# Generated by FakeRAM 2.0
VERSION 5.7 ;
BUSBITCHARS "[]" ;
PROPERTYDEFINITIONS
  MACRO width INTEGER ;
  MACRO depth INTEGER ;
  MACRO banks INTEGER ;
END PROPERTYDEFINITIONS
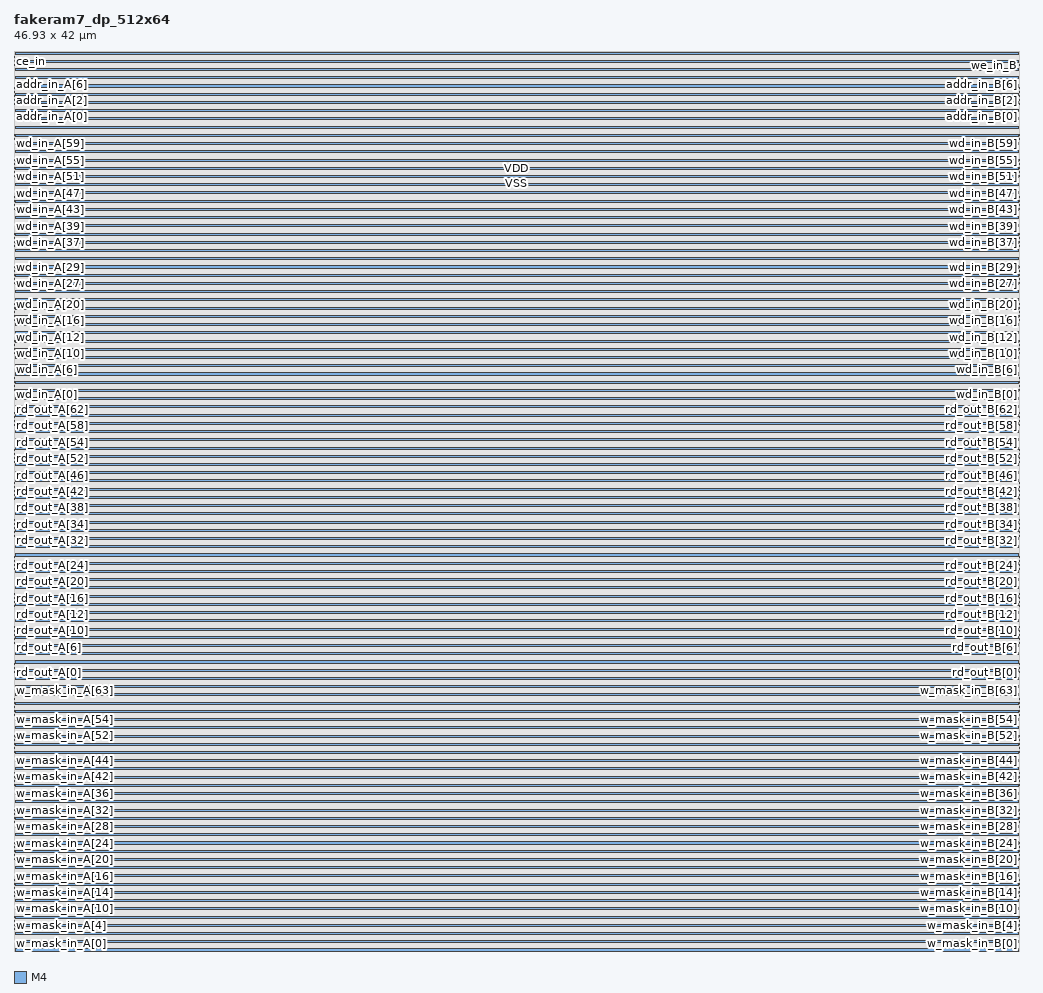
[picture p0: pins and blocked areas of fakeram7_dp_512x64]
MACRO fakeram7_dp_512x64
  PROPERTY width 64 ;
  PROPERTY depth 512 ;
  PROPERTY banks 4 ;
  FOREIGN fakeram7_dp_512x64 0 0 ;
  SYMMETRY X Y ;
  SIZE 46.930 BY 42.000 ;
  CLASS BLOCK ;
  PIN w_mask_in_A[0]
    DIRECTION INPUT ;
    USE SIGNAL ;
    SHAPE ABUTMENT ;
    PORT
      LAYER M4 ;
      RECT 0.000 0.048 0.024 0.072 ;
    END
  END w_mask_in_A[0]
  PIN w_mask_in_B[0]
    DIRECTION INPUT ;
    USE SIGNAL ;
    SHAPE ABUTMENT ;
    PORT
      LAYER M4 ;
      RECT 46.906 0.048 46.930 0.072 ;
    END
  END w_mask_in_B[0]
  PIN w_mask_in_A[1]
    DIRECTION INPUT ;
    USE SIGNAL ;
    SHAPE ABUTMENT ;
    PORT
      LAYER M4 ;
      RECT 0.000 0.240 0.024 0.264 ;
    END
  END w_mask_in_A[1]
  PIN w_mask_in_B[1]
    DIRECTION INPUT ;
    USE SIGNAL ;
    SHAPE ABUTMENT ;
    PORT
      LAYER M4 ;
      RECT 46.906 0.240 46.930 0.264 ;
    END
  END w_mask_in_B[1]
  PIN w_mask_in_A[2]
    DIRECTION INPUT ;
    USE SIGNAL ;
    SHAPE ABUTMENT ;
    PORT
      LAYER M4 ;
      RECT 0.000 0.432 0.024 0.456 ;
    END
  END w_mask_in_A[2]
  PIN w_mask_in_B[2]
    DIRECTION INPUT ;
    USE SIGNAL ;
    SHAPE ABUTMENT ;
    PORT
      LAYER M4 ;
      RECT 46.906 0.432 46.930 0.456 ;
    END
  END w_mask_in_B[2]
  PIN w_mask_in_A[3]
    DIRECTION INPUT ;
    USE SIGNAL ;
    SHAPE ABUTMENT ;
    PORT
      LAYER M4 ;
      RECT 0.000 0.624 0.024 0.648 ;
    END
  END w_mask_in_A[3]
  PIN w_mask_in_B[3]
    DIRECTION INPUT ;
    USE SIGNAL ;
    SHAPE ABUTMENT ;
    PORT
      LAYER M4 ;
      RECT 46.906 0.624 46.930 0.648 ;
    END
  END w_mask_in_B[3]
  PIN w_mask_in_A[4]
    DIRECTION INPUT ;
    USE SIGNAL ;
    SHAPE ABUTMENT ;
    PORT
      LAYER M4 ;
      RECT 0.000 0.816 0.024 0.840 ;
    END
  END w_mask_in_A[4]
  PIN w_mask_in_B[4]
    DIRECTION INPUT ;
    USE SIGNAL ;
    SHAPE ABUTMENT ;
    PORT
      LAYER M4 ;
      RECT 46.906 0.816 46.930 0.840 ;
    END
  END w_mask_in_B[4]
  PIN w_mask_in_A[5]
    DIRECTION INPUT ;
    USE SIGNAL ;
    SHAPE ABUTMENT ;
    PORT
      LAYER M4 ;
      RECT 0.000 1.008 0.024 1.032 ;
    END
  END w_mask_in_A[5]
  PIN w_mask_in_B[5]
    DIRECTION INPUT ;
    USE SIGNAL ;
    SHAPE ABUTMENT ;
    PORT
      LAYER M4 ;
      RECT 46.906 1.008 46.930 1.032 ;
    END
  END w_mask_in_B[5]
  PIN w_mask_in_A[6]
    DIRECTION INPUT ;
    USE SIGNAL ;
    SHAPE ABUTMENT ;
    PORT
      LAYER M4 ;
      RECT 0.000 1.200 0.024 1.224 ;
    END
  END w_mask_in_A[6]
  PIN w_mask_in_B[6]
    DIRECTION INPUT ;
    USE SIGNAL ;
    SHAPE ABUTMENT ;
    PORT
      LAYER M4 ;
      RECT 46.906 1.200 46.930 1.224 ;
    END
  END w_mask_in_B[6]
  PIN w_mask_in_A[7]
    DIRECTION INPUT ;
    USE SIGNAL ;
    SHAPE ABUTMENT ;
    PORT
      LAYER M4 ;
      RECT 0.000 1.392 0.024 1.416 ;
    END
  END w_mask_in_A[7]
  PIN w_mask_in_B[7]
    DIRECTION INPUT ;
    USE SIGNAL ;
    SHAPE ABUTMENT ;
    PORT
      LAYER M4 ;
      RECT 46.906 1.392 46.930 1.416 ;
    END
  END w_mask_in_B[7]
  PIN w_mask_in_A[8]
    DIRECTION INPUT ;
    USE SIGNAL ;
    SHAPE ABUTMENT ;
    PORT
      LAYER M4 ;
      RECT 0.000 1.584 0.024 1.608 ;
    END
  END w_mask_in_A[8]
  PIN w_mask_in_B[8]
    DIRECTION INPUT ;
    USE SIGNAL ;
    SHAPE ABUTMENT ;
    PORT
      LAYER M4 ;
      RECT 46.906 1.584 46.930 1.608 ;
    END
  END w_mask_in_B[8]
  PIN w_mask_in_A[9]
    DIRECTION INPUT ;
    USE SIGNAL ;
    SHAPE ABUTMENT ;
    PORT
      LAYER M4 ;
      RECT 0.000 1.776 0.024 1.800 ;
    END
  END w_mask_in_A[9]
  PIN w_mask_in_B[9]
    DIRECTION INPUT ;
    USE SIGNAL ;
    SHAPE ABUTMENT ;
    PORT
      LAYER M4 ;
      RECT 46.906 1.776 46.930 1.800 ;
    END
  END w_mask_in_B[9]
  PIN w_mask_in_A[10]
    DIRECTION INPUT ;
    USE SIGNAL ;
    SHAPE ABUTMENT ;
    PORT
      LAYER M4 ;
      RECT 0.000 1.968 0.024 1.992 ;
    END
  END w_mask_in_A[10]
  PIN w_mask_in_B[10]
    DIRECTION INPUT ;
    USE SIGNAL ;
    SHAPE ABUTMENT ;
    PORT
      LAYER M4 ;
      RECT 46.906 1.968 46.930 1.992 ;
    END
  END w_mask_in_B[10]
  PIN w_mask_in_A[11]
    DIRECTION INPUT ;
    USE SIGNAL ;
    SHAPE ABUTMENT ;
    PORT
      LAYER M4 ;
      RECT 0.000 2.160 0.024 2.184 ;
    END
  END w_mask_in_A[11]
  PIN w_mask_in_B[11]
    DIRECTION INPUT ;
    USE SIGNAL ;
    SHAPE ABUTMENT ;
    PORT
      LAYER M4 ;
      RECT 46.906 2.160 46.930 2.184 ;
    END
  END w_mask_in_B[11]
  PIN w_mask_in_A[12]
    DIRECTION INPUT ;
    USE SIGNAL ;
    SHAPE ABUTMENT ;
    PORT
      LAYER M4 ;
      RECT 0.000 2.352 0.024 2.376 ;
    END
  END w_mask_in_A[12]
  PIN w_mask_in_B[12]
    DIRECTION INPUT ;
    USE SIGNAL ;
    SHAPE ABUTMENT ;
    PORT
      LAYER M4 ;
      RECT 46.906 2.352 46.930 2.376 ;
    END
  END w_mask_in_B[12]
  PIN w_mask_in_A[13]
    DIRECTION INPUT ;
    USE SIGNAL ;
    SHAPE ABUTMENT ;
    PORT
      LAYER M4 ;
      RECT 0.000 2.544 0.024 2.568 ;
    END
  END w_mask_in_A[13]
  PIN w_mask_in_B[13]
    DIRECTION INPUT ;
    USE SIGNAL ;
    SHAPE ABUTMENT ;
    PORT
      LAYER M4 ;
      RECT 46.906 2.544 46.930 2.568 ;
    END
  END w_mask_in_B[13]
  PIN w_mask_in_A[14]
    DIRECTION INPUT ;
    USE SIGNAL ;
    SHAPE ABUTMENT ;
    PORT
      LAYER M4 ;
      RECT 0.000 2.736 0.024 2.760 ;
    END
  END w_mask_in_A[14]
  PIN w_mask_in_B[14]
    DIRECTION INPUT ;
    USE SIGNAL ;
    SHAPE ABUTMENT ;
    PORT
      LAYER M4 ;
      RECT 46.906 2.736 46.930 2.760 ;
    END
  END w_mask_in_B[14]
  PIN w_mask_in_A[15]
    DIRECTION INPUT ;
    USE SIGNAL ;
    SHAPE ABUTMENT ;
    PORT
      LAYER M4 ;
      RECT 0.000 2.928 0.024 2.952 ;
    END
  END w_mask_in_A[15]
  PIN w_mask_in_B[15]
    DIRECTION INPUT ;
    USE SIGNAL ;
    SHAPE ABUTMENT ;
    PORT
      LAYER M4 ;
      RECT 46.906 2.928 46.930 2.952 ;
    END
  END w_mask_in_B[15]
  PIN w_mask_in_A[16]
    DIRECTION INPUT ;
    USE SIGNAL ;
    SHAPE ABUTMENT ;
    PORT
      LAYER M4 ;
      RECT 0.000 3.120 0.024 3.144 ;
    END
  END w_mask_in_A[16]
  PIN w_mask_in_B[16]
    DIRECTION INPUT ;
    USE SIGNAL ;
    SHAPE ABUTMENT ;
    PORT
      LAYER M4 ;
      RECT 46.906 3.120 46.930 3.144 ;
    END
  END w_mask_in_B[16]
  PIN w_mask_in_A[17]
    DIRECTION INPUT ;
    USE SIGNAL ;
    SHAPE ABUTMENT ;
    PORT
      LAYER M4 ;
      RECT 0.000 3.312 0.024 3.336 ;
    END
  END w_mask_in_A[17]
  PIN w_mask_in_B[17]
    DIRECTION INPUT ;
    USE SIGNAL ;
    SHAPE ABUTMENT ;
    PORT
      LAYER M4 ;
      RECT 46.906 3.312 46.930 3.336 ;
    END
  END w_mask_in_B[17]
  PIN w_mask_in_A[18]
    DIRECTION INPUT ;
    USE SIGNAL ;
    SHAPE ABUTMENT ;
    PORT
      LAYER M4 ;
      RECT 0.000 3.504 0.024 3.528 ;
    END
  END w_mask_in_A[18]
  PIN w_mask_in_B[18]
    DIRECTION INPUT ;
    USE SIGNAL ;
    SHAPE ABUTMENT ;
    PORT
      LAYER M4 ;
      RECT 46.906 3.504 46.930 3.528 ;
    END
  END w_mask_in_B[18]
  PIN w_mask_in_A[19]
    DIRECTION INPUT ;
    USE SIGNAL ;
    SHAPE ABUTMENT ;
    PORT
      LAYER M4 ;
      RECT 0.000 3.696 0.024 3.720 ;
    END
  END w_mask_in_A[19]
  PIN w_mask_in_B[19]
    DIRECTION INPUT ;
    USE SIGNAL ;
    SHAPE ABUTMENT ;
    PORT
      LAYER M4 ;
      RECT 46.906 3.696 46.930 3.720 ;
    END
  END w_mask_in_B[19]
  PIN w_mask_in_A[20]
    DIRECTION INPUT ;
    USE SIGNAL ;
    SHAPE ABUTMENT ;
    PORT
      LAYER M4 ;
      RECT 0.000 3.888 0.024 3.912 ;
    END
  END w_mask_in_A[20]
  PIN w_mask_in_B[20]
    DIRECTION INPUT ;
    USE SIGNAL ;
    SHAPE ABUTMENT ;
    PORT
      LAYER M4 ;
      RECT 46.906 3.888 46.930 3.912 ;
    END
  END w_mask_in_B[20]
  PIN w_mask_in_A[21]
    DIRECTION INPUT ;
    USE SIGNAL ;
    SHAPE ABUTMENT ;
    PORT
      LAYER M4 ;
      RECT 0.000 4.080 0.024 4.104 ;
    END
  END w_mask_in_A[21]
  PIN w_mask_in_B[21]
    DIRECTION INPUT ;
    USE SIGNAL ;
    SHAPE ABUTMENT ;
    PORT
      LAYER M4 ;
      RECT 46.906 4.080 46.930 4.104 ;
    END
  END w_mask_in_B[21]
  PIN w_mask_in_A[22]
    DIRECTION INPUT ;
    USE SIGNAL ;
    SHAPE ABUTMENT ;
    PORT
      LAYER M4 ;
      RECT 0.000 4.272 0.024 4.296 ;
    END
  END w_mask_in_A[22]
  PIN w_mask_in_B[22]
    DIRECTION INPUT ;
    USE SIGNAL ;
    SHAPE ABUTMENT ;
    PORT
      LAYER M4 ;
      RECT 46.906 4.272 46.930 4.296 ;
    END
  END w_mask_in_B[22]
  PIN w_mask_in_A[23]
    DIRECTION INPUT ;
    USE SIGNAL ;
    SHAPE ABUTMENT ;
    PORT
      LAYER M4 ;
      RECT 0.000 4.464 0.024 4.488 ;
    END
  END w_mask_in_A[23]
  PIN w_mask_in_B[23]
    DIRECTION INPUT ;
    USE SIGNAL ;
    SHAPE ABUTMENT ;
    PORT
      LAYER M4 ;
      RECT 46.906 4.464 46.930 4.488 ;
    END
  END w_mask_in_B[23]
  PIN w_mask_in_A[24]
    DIRECTION INPUT ;
    USE SIGNAL ;
    SHAPE ABUTMENT ;
    PORT
      LAYER M4 ;
      RECT 0.000 4.656 0.024 4.680 ;
    END
  END w_mask_in_A[24]
  PIN w_mask_in_B[24]
    DIRECTION INPUT ;
    USE SIGNAL ;
    SHAPE ABUTMENT ;
    PORT
      LAYER M4 ;
      RECT 46.906 4.656 46.930 4.680 ;
    END
  END w_mask_in_B[24]
  PIN w_mask_in_A[25]
    DIRECTION INPUT ;
    USE SIGNAL ;
    SHAPE ABUTMENT ;
    PORT
      LAYER M4 ;
      RECT 0.000 4.848 0.024 4.872 ;
    END
  END w_mask_in_A[25]
  PIN w_mask_in_B[25]
    DIRECTION INPUT ;
    USE SIGNAL ;
    SHAPE ABUTMENT ;
    PORT
      LAYER M4 ;
      RECT 46.906 4.848 46.930 4.872 ;
    END
  END w_mask_in_B[25]
  PIN w_mask_in_A[26]
    DIRECTION INPUT ;
    USE SIGNAL ;
    SHAPE ABUTMENT ;
    PORT
      LAYER M4 ;
      RECT 0.000 5.040 0.024 5.064 ;
    END
  END w_mask_in_A[26]
  PIN w_mask_in_B[26]
    DIRECTION INPUT ;
    USE SIGNAL ;
    SHAPE ABUTMENT ;
    PORT
      LAYER M4 ;
      RECT 46.906 5.040 46.930 5.064 ;
    END
  END w_mask_in_B[26]
  PIN w_mask_in_A[27]
    DIRECTION INPUT ;
    USE SIGNAL ;
    SHAPE ABUTMENT ;
    PORT
      LAYER M4 ;
      RECT 0.000 5.232 0.024 5.256 ;
    END
  END w_mask_in_A[27]
  PIN w_mask_in_B[27]
    DIRECTION INPUT ;
    USE SIGNAL ;
    SHAPE ABUTMENT ;
    PORT
      LAYER M4 ;
      RECT 46.906 5.232 46.930 5.256 ;
    END
  END w_mask_in_B[27]
  PIN w_mask_in_A[28]
    DIRECTION INPUT ;
    USE SIGNAL ;
    SHAPE ABUTMENT ;
    PORT
      LAYER M4 ;
      RECT 0.000 5.424 0.024 5.448 ;
    END
  END w_mask_in_A[28]
  PIN w_mask_in_B[28]
    DIRECTION INPUT ;
    USE SIGNAL ;
    SHAPE ABUTMENT ;
    PORT
      LAYER M4 ;
      RECT 46.906 5.424 46.930 5.448 ;
    END
  END w_mask_in_B[28]
  PIN w_mask_in_A[29]
    DIRECTION INPUT ;
    USE SIGNAL ;
    SHAPE ABUTMENT ;
    PORT
      LAYER M4 ;
      RECT 0.000 5.616 0.024 5.640 ;
    END
  END w_mask_in_A[29]
  PIN w_mask_in_B[29]
    DIRECTION INPUT ;
    USE SIGNAL ;
    SHAPE ABUTMENT ;
    PORT
      LAYER M4 ;
      RECT 46.906 5.616 46.930 5.640 ;
    END
  END w_mask_in_B[29]
  PIN w_mask_in_A[30]
    DIRECTION INPUT ;
    USE SIGNAL ;
    SHAPE ABUTMENT ;
    PORT
      LAYER M4 ;
      RECT 0.000 5.808 0.024 5.832 ;
    END
  END w_mask_in_A[30]
  PIN w_mask_in_B[30]
    DIRECTION INPUT ;
    USE SIGNAL ;
    SHAPE ABUTMENT ;
    PORT
      LAYER M4 ;
      RECT 46.906 5.808 46.930 5.832 ;
    END
  END w_mask_in_B[30]
  PIN w_mask_in_A[31]
    DIRECTION INPUT ;
    USE SIGNAL ;
    SHAPE ABUTMENT ;
    PORT
      LAYER M4 ;
      RECT 0.000 6.000 0.024 6.024 ;
    END
  END w_mask_in_A[31]
  PIN w_mask_in_B[31]
    DIRECTION INPUT ;
    USE SIGNAL ;
    SHAPE ABUTMENT ;
    PORT
      LAYER M4 ;
      RECT 46.906 6.000 46.930 6.024 ;
    END
  END w_mask_in_B[31]
  PIN w_mask_in_A[32]
    DIRECTION INPUT ;
    USE SIGNAL ;
    SHAPE ABUTMENT ;
    PORT
      LAYER M4 ;
      RECT 0.000 6.192 0.024 6.216 ;
    END
  END w_mask_in_A[32]
  PIN w_mask_in_B[32]
    DIRECTION INPUT ;
    USE SIGNAL ;
    SHAPE ABUTMENT ;
    PORT
      LAYER M4 ;
      RECT 46.906 6.192 46.930 6.216 ;
    END
  END w_mask_in_B[32]
  PIN w_mask_in_A[33]
    DIRECTION INPUT ;
    USE SIGNAL ;
    SHAPE ABUTMENT ;
    PORT
      LAYER M4 ;
      RECT 0.000 6.384 0.024 6.408 ;
    END
  END w_mask_in_A[33]
  PIN w_mask_in_B[33]
    DIRECTION INPUT ;
    USE SIGNAL ;
    SHAPE ABUTMENT ;
    PORT
      LAYER M4 ;
      RECT 46.906 6.384 46.930 6.408 ;
    END
  END w_mask_in_B[33]
  PIN w_mask_in_A[34]
    DIRECTION INPUT ;
    USE SIGNAL ;
    SHAPE ABUTMENT ;
    PORT
      LAYER M4 ;
      RECT 0.000 6.576 0.024 6.600 ;
    END
  END w_mask_in_A[34]
  PIN w_mask_in_B[34]
    DIRECTION INPUT ;
    USE SIGNAL ;
    SHAPE ABUTMENT ;
    PORT
      LAYER M4 ;
      RECT 46.906 6.576 46.930 6.600 ;
    END
  END w_mask_in_B[34]
  PIN w_mask_in_A[35]
    DIRECTION INPUT ;
    USE SIGNAL ;
    SHAPE ABUTMENT ;
    PORT
      LAYER M4 ;
      RECT 0.000 6.768 0.024 6.792 ;
    END
  END w_mask_in_A[35]
  PIN w_mask_in_B[35]
    DIRECTION INPUT ;
    USE SIGNAL ;
    SHAPE ABUTMENT ;
    PORT
      LAYER M4 ;
      RECT 46.906 6.768 46.930 6.792 ;
    END
  END w_mask_in_B[35]
  PIN w_mask_in_A[36]
    DIRECTION INPUT ;
    USE SIGNAL ;
    SHAPE ABUTMENT ;
    PORT
      LAYER M4 ;
      RECT 0.000 6.960 0.024 6.984 ;
    END
  END w_mask_in_A[36]
  PIN w_mask_in_B[36]
    DIRECTION INPUT ;
    USE SIGNAL ;
    SHAPE ABUTMENT ;
    PORT
      LAYER M4 ;
      RECT 46.906 6.960 46.930 6.984 ;
    END
  END w_mask_in_B[36]
  PIN w_mask_in_A[37]
    DIRECTION INPUT ;
    USE SIGNAL ;
    SHAPE ABUTMENT ;
    PORT
      LAYER M4 ;
      RECT 0.000 7.152 0.024 7.176 ;
    END
  END w_mask_in_A[37]
  PIN w_mask_in_B[37]
    DIRECTION INPUT ;
    USE SIGNAL ;
    SHAPE ABUTMENT ;
    PORT
      LAYER M4 ;
      RECT 46.906 7.152 46.930 7.176 ;
    END
  END w_mask_in_B[37]
  PIN w_mask_in_A[38]
    DIRECTION INPUT ;
    USE SIGNAL ;
    SHAPE ABUTMENT ;
    PORT
      LAYER M4 ;
      RECT 0.000 7.344 0.024 7.368 ;
    END
  END w_mask_in_A[38]
  PIN w_mask_in_B[38]
    DIRECTION INPUT ;
    USE SIGNAL ;
    SHAPE ABUTMENT ;
    PORT
      LAYER M4 ;
      RECT 46.906 7.344 46.930 7.368 ;
    END
  END w_mask_in_B[38]
  PIN w_mask_in_A[39]
    DIRECTION INPUT ;
    USE SIGNAL ;
    SHAPE ABUTMENT ;
    PORT
      LAYER M4 ;
      RECT 0.000 7.536 0.024 7.560 ;
    END
  END w_mask_in_A[39]
  PIN w_mask_in_B[39]
    DIRECTION INPUT ;
    USE SIGNAL ;
    SHAPE ABUTMENT ;
    PORT
      LAYER M4 ;
      RECT 46.906 7.536 46.930 7.560 ;
    END
  END w_mask_in_B[39]
  PIN w_mask_in_A[40]
    DIRECTION INPUT ;
    USE SIGNAL ;
    SHAPE ABUTMENT ;
    PORT
      LAYER M4 ;
      RECT 0.000 7.728 0.024 7.752 ;
    END
  END w_mask_in_A[40]
  PIN w_mask_in_B[40]
    DIRECTION INPUT ;
    USE SIGNAL ;
    SHAPE ABUTMENT ;
    PORT
      LAYER M4 ;
      RECT 46.906 7.728 46.930 7.752 ;
    END
  END w_mask_in_B[40]
  PIN w_mask_in_A[41]
    DIRECTION INPUT ;
    USE SIGNAL ;
    SHAPE ABUTMENT ;
    PORT
      LAYER M4 ;
      RECT 0.000 7.920 0.024 7.944 ;
    END
  END w_mask_in_A[41]
  PIN w_mask_in_B[41]
    DIRECTION INPUT ;
    USE SIGNAL ;
    SHAPE ABUTMENT ;
    PORT
      LAYER M4 ;
      RECT 46.906 7.920 46.930 7.944 ;
    END
  END w_mask_in_B[41]
  PIN w_mask_in_A[42]
    DIRECTION INPUT ;
    USE SIGNAL ;
    SHAPE ABUTMENT ;
    PORT
      LAYER M4 ;
      RECT 0.000 8.112 0.024 8.136 ;
    END
  END w_mask_in_A[42]
  PIN w_mask_in_B[42]
    DIRECTION INPUT ;
    USE SIGNAL ;
    SHAPE ABUTMENT ;
    PORT
      LAYER M4 ;
      RECT 46.906 8.112 46.930 8.136 ;
    END
  END w_mask_in_B[42]
  PIN w_mask_in_A[43]
    DIRECTION INPUT ;
    USE SIGNAL ;
    SHAPE ABUTMENT ;
    PORT
      LAYER M4 ;
      RECT 0.000 8.304 0.024 8.328 ;
    END
  END w_mask_in_A[43]
  PIN w_mask_in_B[43]
    DIRECTION INPUT ;
    USE SIGNAL ;
    SHAPE ABUTMENT ;
    PORT
      LAYER M4 ;
      RECT 46.906 8.304 46.930 8.328 ;
    END
  END w_mask_in_B[43]
  PIN w_mask_in_A[44]
    DIRECTION INPUT ;
    USE SIGNAL ;
    SHAPE ABUTMENT ;
    PORT
      LAYER M4 ;
      RECT 0.000 8.496 0.024 8.520 ;
    END
  END w_mask_in_A[44]
  PIN w_mask_in_B[44]
    DIRECTION INPUT ;
    USE SIGNAL ;
    SHAPE ABUTMENT ;
    PORT
      LAYER M4 ;
      RECT 46.906 8.496 46.930 8.520 ;
    END
  END w_mask_in_B[44]
  PIN w_mask_in_A[45]
    DIRECTION INPUT ;
    USE SIGNAL ;
    SHAPE ABUTMENT ;
    PORT
      LAYER M4 ;
      RECT 0.000 8.688 0.024 8.712 ;
    END
  END w_mask_in_A[45]
  PIN w_mask_in_B[45]
    DIRECTION INPUT ;
    USE SIGNAL ;
    SHAPE ABUTMENT ;
    PORT
      LAYER M4 ;
      RECT 46.906 8.688 46.930 8.712 ;
    END
  END w_mask_in_B[45]
  PIN w_mask_in_A[46]
    DIRECTION INPUT ;
    USE SIGNAL ;
    SHAPE ABUTMENT ;
    PORT
      LAYER M4 ;
      RECT 0.000 8.880 0.024 8.904 ;
    END
  END w_mask_in_A[46]
  PIN w_mask_in_B[46]
    DIRECTION INPUT ;
    USE SIGNAL ;
    SHAPE ABUTMENT ;
    PORT
      LAYER M4 ;
      RECT 46.906 8.880 46.930 8.904 ;
    END
  END w_mask_in_B[46]
  PIN w_mask_in_A[47]
    DIRECTION INPUT ;
    USE SIGNAL ;
    SHAPE ABUTMENT ;
    PORT
      LAYER M4 ;
      RECT 0.000 9.072 0.024 9.096 ;
    END
  END w_mask_in_A[47]
  PIN w_mask_in_B[47]
    DIRECTION INPUT ;
    USE SIGNAL ;
    SHAPE ABUTMENT ;
    PORT
      LAYER M4 ;
      RECT 46.906 9.072 46.930 9.096 ;
    END
  END w_mask_in_B[47]
  PIN w_mask_in_A[48]
    DIRECTION INPUT ;
    USE SIGNAL ;
    SHAPE ABUTMENT ;
    PORT
      LAYER M4 ;
      RECT 0.000 9.264 0.024 9.288 ;
    END
  END w_mask_in_A[48]
  PIN w_mask_in_B[48]
    DIRECTION INPUT ;
    USE SIGNAL ;
    SHAPE ABUTMENT ;
    PORT
      LAYER M4 ;
      RECT 46.906 9.264 46.930 9.288 ;
    END
  END w_mask_in_B[48]
  PIN w_mask_in_A[49]
    DIRECTION INPUT ;
    USE SIGNAL ;
    SHAPE ABUTMENT ;
    PORT
      LAYER M4 ;
      RECT 0.000 9.456 0.024 9.480 ;
    END
  END w_mask_in_A[49]
  PIN w_mask_in_B[49]
    DIRECTION INPUT ;
    USE SIGNAL ;
    SHAPE ABUTMENT ;
    PORT
      LAYER M4 ;
      RECT 46.906 9.456 46.930 9.480 ;
    END
  END w_mask_in_B[49]
  PIN w_mask_in_A[50]
    DIRECTION INPUT ;
    USE SIGNAL ;
    SHAPE ABUTMENT ;
    PORT
      LAYER M4 ;
      RECT 0.000 9.648 0.024 9.672 ;
    END
  END w_mask_in_A[50]
  PIN w_mask_in_B[50]
    DIRECTION INPUT ;
    USE SIGNAL ;
    SHAPE ABUTMENT ;
    PORT
      LAYER M4 ;
      RECT 46.906 9.648 46.930 9.672 ;
    END
  END w_mask_in_B[50]
  PIN w_mask_in_A[51]
    DIRECTION INPUT ;
    USE SIGNAL ;
    SHAPE ABUTMENT ;
    PORT
      LAYER M4 ;
      RECT 0.000 9.840 0.024 9.864 ;
    END
  END w_mask_in_A[51]
  PIN w_mask_in_B[51]
    DIRECTION INPUT ;
    USE SIGNAL ;
    SHAPE ABUTMENT ;
    PORT
      LAYER M4 ;
      RECT 46.906 9.840 46.930 9.864 ;
    END
  END w_mask_in_B[51]
  PIN w_mask_in_A[52]
    DIRECTION INPUT ;
    USE SIGNAL ;
    SHAPE ABUTMENT ;
    PORT
      LAYER M4 ;
      RECT 0.000 10.032 0.024 10.056 ;
    END
  END w_mask_in_A[52]
  PIN w_mask_in_B[52]
    DIRECTION INPUT ;
    USE SIGNAL ;
    SHAPE ABUTMENT ;
    PORT
      LAYER M4 ;
      RECT 46.906 10.032 46.930 10.056 ;
    END
  END w_mask_in_B[52]
  PIN w_mask_in_A[53]
    DIRECTION INPUT ;
    USE SIGNAL ;
    SHAPE ABUTMENT ;
    PORT
      LAYER M4 ;
      RECT 0.000 10.224 0.024 10.248 ;
    END
  END w_mask_in_A[53]
  PIN w_mask_in_B[53]
    DIRECTION INPUT ;
    USE SIGNAL ;
    SHAPE ABUTMENT ;
    PORT
      LAYER M4 ;
      RECT 46.906 10.224 46.930 10.248 ;
    END
  END w_mask_in_B[53]
  PIN w_mask_in_A[54]
    DIRECTION INPUT ;
    USE SIGNAL ;
    SHAPE ABUTMENT ;
    PORT
      LAYER M4 ;
      RECT 0.000 10.416 0.024 10.440 ;
    END
  END w_mask_in_A[54]
  PIN w_mask_in_B[54]
    DIRECTION INPUT ;
    USE SIGNAL ;
    SHAPE ABUTMENT ;
    PORT
      LAYER M4 ;
      RECT 46.906 10.416 46.930 10.440 ;
    END
  END w_mask_in_B[54]
  PIN w_mask_in_A[55]
    DIRECTION INPUT ;
    USE SIGNAL ;
    SHAPE ABUTMENT ;
    PORT
      LAYER M4 ;
      RECT 0.000 10.608 0.024 10.632 ;
    END
  END w_mask_in_A[55]
  PIN w_mask_in_B[55]
    DIRECTION INPUT ;
    USE SIGNAL ;
    SHAPE ABUTMENT ;
    PORT
      LAYER M4 ;
      RECT 46.906 10.608 46.930 10.632 ;
    END
  END w_mask_in_B[55]
  PIN w_mask_in_A[56]
    DIRECTION INPUT ;
    USE SIGNAL ;
    SHAPE ABUTMENT ;
    PORT
      LAYER M4 ;
      RECT 0.000 10.800 0.024 10.824 ;
    END
  END w_mask_in_A[56]
  PIN w_mask_in_B[56]
    DIRECTION INPUT ;
    USE SIGNAL ;
    SHAPE ABUTMENT ;
    PORT
      LAYER M4 ;
      RECT 46.906 10.800 46.930 10.824 ;
    END
  END w_mask_in_B[56]
  PIN w_mask_in_A[57]
    DIRECTION INPUT ;
    USE SIGNAL ;
    SHAPE ABUTMENT ;
    PORT
      LAYER M4 ;
      RECT 0.000 10.992 0.024 11.016 ;
    END
  END w_mask_in_A[57]
  PIN w_mask_in_B[57]
    DIRECTION INPUT ;
    USE SIGNAL ;
    SHAPE ABUTMENT ;
    PORT
      LAYER M4 ;
      RECT 46.906 10.992 46.930 11.016 ;
    END
  END w_mask_in_B[57]
  PIN w_mask_in_A[58]
    DIRECTION INPUT ;
    USE SIGNAL ;
    SHAPE ABUTMENT ;
    PORT
      LAYER M4 ;
      RECT 0.000 11.184 0.024 11.208 ;
    END
  END w_mask_in_A[58]
  PIN w_mask_in_B[58]
    DIRECTION INPUT ;
    USE SIGNAL ;
    SHAPE ABUTMENT ;
    PORT
      LAYER M4 ;
      RECT 46.906 11.184 46.930 11.208 ;
    END
  END w_mask_in_B[58]
  PIN w_mask_in_A[59]
    DIRECTION INPUT ;
    USE SIGNAL ;
    SHAPE ABUTMENT ;
    PORT
      LAYER M4 ;
      RECT 0.000 11.376 0.024 11.400 ;
    END
  END w_mask_in_A[59]
  PIN w_mask_in_B[59]
    DIRECTION INPUT ;
    USE SIGNAL ;
    SHAPE ABUTMENT ;
    PORT
      LAYER M4 ;
      RECT 46.906 11.376 46.930 11.400 ;
    END
  END w_mask_in_B[59]
  PIN w_mask_in_A[60]
    DIRECTION INPUT ;
    USE SIGNAL ;
    SHAPE ABUTMENT ;
    PORT
      LAYER M4 ;
      RECT 0.000 11.568 0.024 11.592 ;
    END
  END w_mask_in_A[60]
  PIN w_mask_in_B[60]
    DIRECTION INPUT ;
    USE SIGNAL ;
    SHAPE ABUTMENT ;
    PORT
      LAYER M4 ;
      RECT 46.906 11.568 46.930 11.592 ;
    END
  END w_mask_in_B[60]
  PIN w_mask_in_A[61]
    DIRECTION INPUT ;
    USE SIGNAL ;
    SHAPE ABUTMENT ;
    PORT
      LAYER M4 ;
      RECT 0.000 11.760 0.024 11.784 ;
    END
  END w_mask_in_A[61]
  PIN w_mask_in_B[61]
    DIRECTION INPUT ;
    USE SIGNAL ;
    SHAPE ABUTMENT ;
    PORT
      LAYER M4 ;
      RECT 46.906 11.760 46.930 11.784 ;
    END
  END w_mask_in_B[61]
  PIN w_mask_in_A[62]
    DIRECTION INPUT ;
    USE SIGNAL ;
    SHAPE ABUTMENT ;
    PORT
      LAYER M4 ;
      RECT 0.000 11.952 0.024 11.976 ;
    END
  END w_mask_in_A[62]
  PIN w_mask_in_B[62]
    DIRECTION INPUT ;
    USE SIGNAL ;
    SHAPE ABUTMENT ;
    PORT
      LAYER M4 ;
      RECT 46.906 11.952 46.930 11.976 ;
    END
  END w_mask_in_B[62]
  PIN w_mask_in_A[63]
    DIRECTION INPUT ;
    USE SIGNAL ;
    SHAPE ABUTMENT ;
    PORT
      LAYER M4 ;
      RECT 0.000 12.144 0.024 12.168 ;
    END
  END w_mask_in_A[63]
  PIN w_mask_in_B[63]
    DIRECTION INPUT ;
    USE SIGNAL ;
    SHAPE ABUTMENT ;
    PORT
      LAYER M4 ;
      RECT 46.906 12.144 46.930 12.168 ;
    END
  END w_mask_in_B[63]
  PIN rd_out_A[0]
    DIRECTION OUTPUT ;
    USE SIGNAL ;
    SHAPE ABUTMENT ;
    PORT
      LAYER M4 ;
      RECT 0.000 13.008 0.024 13.032 ;
    END
  END rd_out_A[0]
  PIN rd_out_B[0]
    DIRECTION OUTPUT ;
    USE SIGNAL ;
    SHAPE ABUTMENT ;
    PORT
      LAYER M4 ;
      RECT 46.906 13.008 46.930 13.032 ;
    END
  END rd_out_B[0]
  PIN rd_out_A[1]
    DIRECTION OUTPUT ;
    USE SIGNAL ;
    SHAPE ABUTMENT ;
    PORT
      LAYER M4 ;
      RECT 0.000 13.200 0.024 13.224 ;
    END
  END rd_out_A[1]
  PIN rd_out_B[1]
    DIRECTION OUTPUT ;
    USE SIGNAL ;
    SHAPE ABUTMENT ;
    PORT
      LAYER M4 ;
      RECT 46.906 13.200 46.930 13.224 ;
    END
  END rd_out_B[1]
  PIN rd_out_A[2]
    DIRECTION OUTPUT ;
    USE SIGNAL ;
    SHAPE ABUTMENT ;
    PORT
      LAYER M4 ;
      RECT 0.000 13.392 0.024 13.416 ;
    END
  END rd_out_A[2]
  PIN rd_out_B[2]
    DIRECTION OUTPUT ;
    USE SIGNAL ;
    SHAPE ABUTMENT ;
    PORT
      LAYER M4 ;
      RECT 46.906 13.392 46.930 13.416 ;
    END
  END rd_out_B[2]
  PIN rd_out_A[3]
    DIRECTION OUTPUT ;
    USE SIGNAL ;
    SHAPE ABUTMENT ;
    PORT
      LAYER M4 ;
      RECT 0.000 13.584 0.024 13.608 ;
    END
  END rd_out_A[3]
  PIN rd_out_B[3]
    DIRECTION OUTPUT ;
    USE SIGNAL ;
    SHAPE ABUTMENT ;
    PORT
      LAYER M4 ;
      RECT 46.906 13.584 46.930 13.608 ;
    END
  END rd_out_B[3]
  PIN rd_out_A[4]
    DIRECTION OUTPUT ;
    USE SIGNAL ;
    SHAPE ABUTMENT ;
    PORT
      LAYER M4 ;
      RECT 0.000 13.776 0.024 13.800 ;
    END
  END rd_out_A[4]
  PIN rd_out_B[4]
    DIRECTION OUTPUT ;
    USE SIGNAL ;
    SHAPE ABUTMENT ;
    PORT
      LAYER M4 ;
      RECT 46.906 13.776 46.930 13.800 ;
    END
  END rd_out_B[4]
  PIN rd_out_A[5]
    DIRECTION OUTPUT ;
    USE SIGNAL ;
    SHAPE ABUTMENT ;
    PORT
      LAYER M4 ;
      RECT 0.000 13.968 0.024 13.992 ;
    END
  END rd_out_A[5]
  PIN rd_out_B[5]
    DIRECTION OUTPUT ;
    USE SIGNAL ;
    SHAPE ABUTMENT ;
    PORT
      LAYER M4 ;
      RECT 46.906 13.968 46.930 13.992 ;
    END
  END rd_out_B[5]
  PIN rd_out_A[6]
    DIRECTION OUTPUT ;
    USE SIGNAL ;
    SHAPE ABUTMENT ;
    PORT
      LAYER M4 ;
      RECT 0.000 14.160 0.024 14.184 ;
    END
  END rd_out_A[6]
  PIN rd_out_B[6]
    DIRECTION OUTPUT ;
    USE SIGNAL ;
    SHAPE ABUTMENT ;
    PORT
      LAYER M4 ;
      RECT 46.906 14.160 46.930 14.184 ;
    END
  END rd_out_B[6]
  PIN rd_out_A[7]
    DIRECTION OUTPUT ;
    USE SIGNAL ;
    SHAPE ABUTMENT ;
    PORT
      LAYER M4 ;
      RECT 0.000 14.352 0.024 14.376 ;
    END
  END rd_out_A[7]
  PIN rd_out_B[7]
    DIRECTION OUTPUT ;
    USE SIGNAL ;
    SHAPE ABUTMENT ;
    PORT
      LAYER M4 ;
      RECT 46.906 14.352 46.930 14.376 ;
    END
  END rd_out_B[7]
  PIN rd_out_A[8]
    DIRECTION OUTPUT ;
    USE SIGNAL ;
    SHAPE ABUTMENT ;
    PORT
      LAYER M4 ;
      RECT 0.000 14.544 0.024 14.568 ;
    END
  END rd_out_A[8]
  PIN rd_out_B[8]
    DIRECTION OUTPUT ;
    USE SIGNAL ;
    SHAPE ABUTMENT ;
    PORT
      LAYER M4 ;
      RECT 46.906 14.544 46.930 14.568 ;
    END
  END rd_out_B[8]
  PIN rd_out_A[9]
    DIRECTION OUTPUT ;
    USE SIGNAL ;
    SHAPE ABUTMENT ;
    PORT
      LAYER M4 ;
      RECT 0.000 14.736 0.024 14.760 ;
    END
  END rd_out_A[9]
  PIN rd_out_B[9]
    DIRECTION OUTPUT ;
    USE SIGNAL ;
    SHAPE ABUTMENT ;
    PORT
      LAYER M4 ;
      RECT 46.906 14.736 46.930 14.760 ;
    END
  END rd_out_B[9]
  PIN rd_out_A[10]
    DIRECTION OUTPUT ;
    USE SIGNAL ;
    SHAPE ABUTMENT ;
    PORT
      LAYER M4 ;
      RECT 0.000 14.928 0.024 14.952 ;
    END
  END rd_out_A[10]
  PIN rd_out_B[10]
    DIRECTION OUTPUT ;
    USE SIGNAL ;
    SHAPE ABUTMENT ;
    PORT
      LAYER M4 ;
      RECT 46.906 14.928 46.930 14.952 ;
    END
  END rd_out_B[10]
  PIN rd_out_A[11]
    DIRECTION OUTPUT ;
    USE SIGNAL ;
    SHAPE ABUTMENT ;
    PORT
      LAYER M4 ;
      RECT 0.000 15.120 0.024 15.144 ;
    END
  END rd_out_A[11]
  PIN rd_out_B[11]
    DIRECTION OUTPUT ;
    USE SIGNAL ;
    SHAPE ABUTMENT ;
    PORT
      LAYER M4 ;
      RECT 46.906 15.120 46.930 15.144 ;
    END
  END rd_out_B[11]
  PIN rd_out_A[12]
    DIRECTION OUTPUT ;
    USE SIGNAL ;
    SHAPE ABUTMENT ;
    PORT
      LAYER M4 ;
      RECT 0.000 15.312 0.024 15.336 ;
    END
  END rd_out_A[12]
  PIN rd_out_B[12]
    DIRECTION OUTPUT ;
    USE SIGNAL ;
    SHAPE ABUTMENT ;
    PORT
      LAYER M4 ;
      RECT 46.906 15.312 46.930 15.336 ;
    END
  END rd_out_B[12]
  PIN rd_out_A[13]
    DIRECTION OUTPUT ;
    USE SIGNAL ;
    SHAPE ABUTMENT ;
    PORT
      LAYER M4 ;
      RECT 0.000 15.504 0.024 15.528 ;
    END
  END rd_out_A[13]
  PIN rd_out_B[13]
    DIRECTION OUTPUT ;
    USE SIGNAL ;
    SHAPE ABUTMENT ;
    PORT
      LAYER M4 ;
      RECT 46.906 15.504 46.930 15.528 ;
    END
  END rd_out_B[13]
  PIN rd_out_A[14]
    DIRECTION OUTPUT ;
    USE SIGNAL ;
    SHAPE ABUTMENT ;
    PORT
      LAYER M4 ;
      RECT 0.000 15.696 0.024 15.720 ;
    END
  END rd_out_A[14]
  PIN rd_out_B[14]
    DIRECTION OUTPUT ;
    USE SIGNAL ;
    SHAPE ABUTMENT ;
    PORT
      LAYER M4 ;
      RECT 46.906 15.696 46.930 15.720 ;
    END
  END rd_out_B[14]
  PIN rd_out_A[15]
    DIRECTION OUTPUT ;
    USE SIGNAL ;
    SHAPE ABUTMENT ;
    PORT
      LAYER M4 ;
      RECT 0.000 15.888 0.024 15.912 ;
    END
  END rd_out_A[15]
  PIN rd_out_B[15]
    DIRECTION OUTPUT ;
    USE SIGNAL ;
    SHAPE ABUTMENT ;
    PORT
      LAYER M4 ;
      RECT 46.906 15.888 46.930 15.912 ;
    END
  END rd_out_B[15]
  PIN rd_out_A[16]
    DIRECTION OUTPUT ;
    USE SIGNAL ;
    SHAPE ABUTMENT ;
    PORT
      LAYER M4 ;
      RECT 0.000 16.080 0.024 16.104 ;
    END
  END rd_out_A[16]
  PIN rd_out_B[16]
    DIRECTION OUTPUT ;
    USE SIGNAL ;
    SHAPE ABUTMENT ;
    PORT
      LAYER M4 ;
      RECT 46.906 16.080 46.930 16.104 ;
    END
  END rd_out_B[16]
  PIN rd_out_A[17]
    DIRECTION OUTPUT ;
    USE SIGNAL ;
    SHAPE ABUTMENT ;
    PORT
      LAYER M4 ;
      RECT 0.000 16.272 0.024 16.296 ;
    END
  END rd_out_A[17]
  PIN rd_out_B[17]
    DIRECTION OUTPUT ;
    USE SIGNAL ;
    SHAPE ABUTMENT ;
    PORT
      LAYER M4 ;
      RECT 46.906 16.272 46.930 16.296 ;
    END
  END rd_out_B[17]
  PIN rd_out_A[18]
    DIRECTION OUTPUT ;
    USE SIGNAL ;
    SHAPE ABUTMENT ;
    PORT
      LAYER M4 ;
      RECT 0.000 16.464 0.024 16.488 ;
    END
  END rd_out_A[18]
  PIN rd_out_B[18]
    DIRECTION OUTPUT ;
    USE SIGNAL ;
    SHAPE ABUTMENT ;
    PORT
      LAYER M4 ;
      RECT 46.906 16.464 46.930 16.488 ;
    END
  END rd_out_B[18]
  PIN rd_out_A[19]
    DIRECTION OUTPUT ;
    USE SIGNAL ;
    SHAPE ABUTMENT ;
    PORT
      LAYER M4 ;
      RECT 0.000 16.656 0.024 16.680 ;
    END
  END rd_out_A[19]
  PIN rd_out_B[19]
    DIRECTION OUTPUT ;
    USE SIGNAL ;
    SHAPE ABUTMENT ;
    PORT
      LAYER M4 ;
      RECT 46.906 16.656 46.930 16.680 ;
    END
  END rd_out_B[19]
  PIN rd_out_A[20]
    DIRECTION OUTPUT ;
    USE SIGNAL ;
    SHAPE ABUTMENT ;
    PORT
      LAYER M4 ;
      RECT 0.000 16.848 0.024 16.872 ;
    END
  END rd_out_A[20]
  PIN rd_out_B[20]
    DIRECTION OUTPUT ;
    USE SIGNAL ;
    SHAPE ABUTMENT ;
    PORT
      LAYER M4 ;
      RECT 46.906 16.848 46.930 16.872 ;
    END
  END rd_out_B[20]
  PIN rd_out_A[21]
    DIRECTION OUTPUT ;
    USE SIGNAL ;
    SHAPE ABUTMENT ;
    PORT
      LAYER M4 ;
      RECT 0.000 17.040 0.024 17.064 ;
    END
  END rd_out_A[21]
  PIN rd_out_B[21]
    DIRECTION OUTPUT ;
    USE SIGNAL ;
    SHAPE ABUTMENT ;
    PORT
      LAYER M4 ;
      RECT 46.906 17.040 46.930 17.064 ;
    END
  END rd_out_B[21]
  PIN rd_out_A[22]
    DIRECTION OUTPUT ;
    USE SIGNAL ;
    SHAPE ABUTMENT ;
    PORT
      LAYER M4 ;
      RECT 0.000 17.232 0.024 17.256 ;
    END
  END rd_out_A[22]
  PIN rd_out_B[22]
    DIRECTION OUTPUT ;
    USE SIGNAL ;
    SHAPE ABUTMENT ;
    PORT
      LAYER M4 ;
      RECT 46.906 17.232 46.930 17.256 ;
    END
  END rd_out_B[22]
  PIN rd_out_A[23]
    DIRECTION OUTPUT ;
    USE SIGNAL ;
    SHAPE ABUTMENT ;
    PORT
      LAYER M4 ;
      RECT 0.000 17.424 0.024 17.448 ;
    END
  END rd_out_A[23]
  PIN rd_out_B[23]
    DIRECTION OUTPUT ;
    USE SIGNAL ;
    SHAPE ABUTMENT ;
    PORT
      LAYER M4 ;
      RECT 46.906 17.424 46.930 17.448 ;
    END
  END rd_out_B[23]
  PIN rd_out_A[24]
    DIRECTION OUTPUT ;
    USE SIGNAL ;
    SHAPE ABUTMENT ;
    PORT
      LAYER M4 ;
      RECT 0.000 17.616 0.024 17.640 ;
    END
  END rd_out_A[24]
  PIN rd_out_B[24]
    DIRECTION OUTPUT ;
    USE SIGNAL ;
    SHAPE ABUTMENT ;
    PORT
      LAYER M4 ;
      RECT 46.906 17.616 46.930 17.640 ;
    END
  END rd_out_B[24]
  PIN rd_out_A[25]
    DIRECTION OUTPUT ;
    USE SIGNAL ;
    SHAPE ABUTMENT ;
    PORT
      LAYER M4 ;
      RECT 0.000 17.808 0.024 17.832 ;
    END
  END rd_out_A[25]
  PIN rd_out_B[25]
    DIRECTION OUTPUT ;
    USE SIGNAL ;
    SHAPE ABUTMENT ;
    PORT
      LAYER M4 ;
      RECT 46.906 17.808 46.930 17.832 ;
    END
  END rd_out_B[25]
  PIN rd_out_A[26]
    DIRECTION OUTPUT ;
    USE SIGNAL ;
    SHAPE ABUTMENT ;
    PORT
      LAYER M4 ;
      RECT 0.000 18.000 0.024 18.024 ;
    END
  END rd_out_A[26]
  PIN rd_out_B[26]
    DIRECTION OUTPUT ;
    USE SIGNAL ;
    SHAPE ABUTMENT ;
    PORT
      LAYER M4 ;
      RECT 46.906 18.000 46.930 18.024 ;
    END
  END rd_out_B[26]
  PIN rd_out_A[27]
    DIRECTION OUTPUT ;
    USE SIGNAL ;
    SHAPE ABUTMENT ;
    PORT
      LAYER M4 ;
      RECT 0.000 18.192 0.024 18.216 ;
    END
  END rd_out_A[27]
  PIN rd_out_B[27]
    DIRECTION OUTPUT ;
    USE SIGNAL ;
    SHAPE ABUTMENT ;
    PORT
      LAYER M4 ;
      RECT 46.906 18.192 46.930 18.216 ;
    END
  END rd_out_B[27]
  PIN rd_out_A[28]
    DIRECTION OUTPUT ;
    USE SIGNAL ;
    SHAPE ABUTMENT ;
    PORT
      LAYER M4 ;
      RECT 0.000 18.384 0.024 18.408 ;
    END
  END rd_out_A[28]
  PIN rd_out_B[28]
    DIRECTION OUTPUT ;
    USE SIGNAL ;
    SHAPE ABUTMENT ;
    PORT
      LAYER M4 ;
      RECT 46.906 18.384 46.930 18.408 ;
    END
  END rd_out_B[28]
  PIN rd_out_A[29]
    DIRECTION OUTPUT ;
    USE SIGNAL ;
    SHAPE ABUTMENT ;
    PORT
      LAYER M4 ;
      RECT 0.000 18.576 0.024 18.600 ;
    END
  END rd_out_A[29]
  PIN rd_out_B[29]
    DIRECTION OUTPUT ;
    USE SIGNAL ;
    SHAPE ABUTMENT ;
    PORT
      LAYER M4 ;
      RECT 46.906 18.576 46.930 18.600 ;
    END
  END rd_out_B[29]
  PIN rd_out_A[30]
    DIRECTION OUTPUT ;
    USE SIGNAL ;
    SHAPE ABUTMENT ;
    PORT
      LAYER M4 ;
      RECT 0.000 18.768 0.024 18.792 ;
    END
  END rd_out_A[30]
  PIN rd_out_B[30]
    DIRECTION OUTPUT ;
    USE SIGNAL ;
    SHAPE ABUTMENT ;
    PORT
      LAYER M4 ;
      RECT 46.906 18.768 46.930 18.792 ;
    END
  END rd_out_B[30]
  PIN rd_out_A[31]
    DIRECTION OUTPUT ;
    USE SIGNAL ;
    SHAPE ABUTMENT ;
    PORT
      LAYER M4 ;
      RECT 0.000 18.960 0.024 18.984 ;
    END
  END rd_out_A[31]
  PIN rd_out_B[31]
    DIRECTION OUTPUT ;
    USE SIGNAL ;
    SHAPE ABUTMENT ;
    PORT
      LAYER M4 ;
      RECT 46.906 18.960 46.930 18.984 ;
    END
  END rd_out_B[31]
  PIN rd_out_A[32]
    DIRECTION OUTPUT ;
    USE SIGNAL ;
    SHAPE ABUTMENT ;
    PORT
      LAYER M4 ;
      RECT 0.000 19.152 0.024 19.176 ;
    END
  END rd_out_A[32]
  PIN rd_out_B[32]
    DIRECTION OUTPUT ;
    USE SIGNAL ;
    SHAPE ABUTMENT ;
    PORT
      LAYER M4 ;
      RECT 46.906 19.152 46.930 19.176 ;
    END
  END rd_out_B[32]
  PIN rd_out_A[33]
    DIRECTION OUTPUT ;
    USE SIGNAL ;
    SHAPE ABUTMENT ;
    PORT
      LAYER M4 ;
      RECT 0.000 19.344 0.024 19.368 ;
    END
  END rd_out_A[33]
  PIN rd_out_B[33]
    DIRECTION OUTPUT ;
    USE SIGNAL ;
    SHAPE ABUTMENT ;
    PORT
      LAYER M4 ;
      RECT 46.906 19.344 46.930 19.368 ;
    END
  END rd_out_B[33]
  PIN rd_out_A[34]
    DIRECTION OUTPUT ;
    USE SIGNAL ;
    SHAPE ABUTMENT ;
    PORT
      LAYER M4 ;
      RECT 0.000 19.536 0.024 19.560 ;
    END
  END rd_out_A[34]
  PIN rd_out_B[34]
    DIRECTION OUTPUT ;
    USE SIGNAL ;
    SHAPE ABUTMENT ;
    PORT
      LAYER M4 ;
      RECT 46.906 19.536 46.930 19.560 ;
    END
  END rd_out_B[34]
  PIN rd_out_A[35]
    DIRECTION OUTPUT ;
    USE SIGNAL ;
    SHAPE ABUTMENT ;
    PORT
      LAYER M4 ;
      RECT 0.000 19.728 0.024 19.752 ;
    END
  END rd_out_A[35]
  PIN rd_out_B[35]
    DIRECTION OUTPUT ;
    USE SIGNAL ;
    SHAPE ABUTMENT ;
    PORT
      LAYER M4 ;
      RECT 46.906 19.728 46.930 19.752 ;
    END
  END rd_out_B[35]
  PIN rd_out_A[36]
    DIRECTION OUTPUT ;
    USE SIGNAL ;
    SHAPE ABUTMENT ;
    PORT
      LAYER M4 ;
      RECT 0.000 19.920 0.024 19.944 ;
    END
  END rd_out_A[36]
  PIN rd_out_B[36]
    DIRECTION OUTPUT ;
    USE SIGNAL ;
    SHAPE ABUTMENT ;
    PORT
      LAYER M4 ;
      RECT 46.906 19.920 46.930 19.944 ;
    END
  END rd_out_B[36]
  PIN rd_out_A[37]
    DIRECTION OUTPUT ;
    USE SIGNAL ;
    SHAPE ABUTMENT ;
    PORT
      LAYER M4 ;
      RECT 0.000 20.112 0.024 20.136 ;
    END
  END rd_out_A[37]
  PIN rd_out_B[37]
    DIRECTION OUTPUT ;
    USE SIGNAL ;
    SHAPE ABUTMENT ;
    PORT
      LAYER M4 ;
      RECT 46.906 20.112 46.930 20.136 ;
    END
  END rd_out_B[37]
  PIN rd_out_A[38]
    DIRECTION OUTPUT ;
    USE SIGNAL ;
    SHAPE ABUTMENT ;
    PORT
      LAYER M4 ;
      RECT 0.000 20.304 0.024 20.328 ;
    END
  END rd_out_A[38]
  PIN rd_out_B[38]
    DIRECTION OUTPUT ;
    USE SIGNAL ;
    SHAPE ABUTMENT ;
    PORT
      LAYER M4 ;
      RECT 46.906 20.304 46.930 20.328 ;
    END
  END rd_out_B[38]
  PIN rd_out_A[39]
    DIRECTION OUTPUT ;
    USE SIGNAL ;
    SHAPE ABUTMENT ;
    PORT
      LAYER M4 ;
      RECT 0.000 20.496 0.024 20.520 ;
    END
  END rd_out_A[39]
  PIN rd_out_B[39]
    DIRECTION OUTPUT ;
    USE SIGNAL ;
    SHAPE ABUTMENT ;
    PORT
      LAYER M4 ;
      RECT 46.906 20.496 46.930 20.520 ;
    END
  END rd_out_B[39]
  PIN rd_out_A[40]
    DIRECTION OUTPUT ;
    USE SIGNAL ;
    SHAPE ABUTMENT ;
    PORT
      LAYER M4 ;
      RECT 0.000 20.688 0.024 20.712 ;
    END
  END rd_out_A[40]
  PIN rd_out_B[40]
    DIRECTION OUTPUT ;
    USE SIGNAL ;
    SHAPE ABUTMENT ;
    PORT
      LAYER M4 ;
      RECT 46.906 20.688 46.930 20.712 ;
    END
  END rd_out_B[40]
  PIN rd_out_A[41]
    DIRECTION OUTPUT ;
    USE SIGNAL ;
    SHAPE ABUTMENT ;
    PORT
      LAYER M4 ;
      RECT 0.000 20.880 0.024 20.904 ;
    END
  END rd_out_A[41]
  PIN rd_out_B[41]
    DIRECTION OUTPUT ;
    USE SIGNAL ;
    SHAPE ABUTMENT ;
    PORT
      LAYER M4 ;
      RECT 46.906 20.880 46.930 20.904 ;
    END
  END rd_out_B[41]
  PIN rd_out_A[42]
    DIRECTION OUTPUT ;
    USE SIGNAL ;
    SHAPE ABUTMENT ;
    PORT
      LAYER M4 ;
      RECT 0.000 21.072 0.024 21.096 ;
    END
  END rd_out_A[42]
  PIN rd_out_B[42]
    DIRECTION OUTPUT ;
    USE SIGNAL ;
    SHAPE ABUTMENT ;
    PORT
      LAYER M4 ;
      RECT 46.906 21.072 46.930 21.096 ;
    END
  END rd_out_B[42]
  PIN rd_out_A[43]
    DIRECTION OUTPUT ;
    USE SIGNAL ;
    SHAPE ABUTMENT ;
    PORT
      LAYER M4 ;
      RECT 0.000 21.264 0.024 21.288 ;
    END
  END rd_out_A[43]
  PIN rd_out_B[43]
    DIRECTION OUTPUT ;
    USE SIGNAL ;
    SHAPE ABUTMENT ;
    PORT
      LAYER M4 ;
      RECT 46.906 21.264 46.930 21.288 ;
    END
  END rd_out_B[43]
  PIN rd_out_A[44]
    DIRECTION OUTPUT ;
    USE SIGNAL ;
    SHAPE ABUTMENT ;
    PORT
      LAYER M4 ;
      RECT 0.000 21.456 0.024 21.480 ;
    END
  END rd_out_A[44]
  PIN rd_out_B[44]
    DIRECTION OUTPUT ;
    USE SIGNAL ;
    SHAPE ABUTMENT ;
    PORT
      LAYER M4 ;
      RECT 46.906 21.456 46.930 21.480 ;
    END
  END rd_out_B[44]
  PIN rd_out_A[45]
    DIRECTION OUTPUT ;
    USE SIGNAL ;
    SHAPE ABUTMENT ;
    PORT
      LAYER M4 ;
      RECT 0.000 21.648 0.024 21.672 ;
    END
  END rd_out_A[45]
  PIN rd_out_B[45]
    DIRECTION OUTPUT ;
    USE SIGNAL ;
    SHAPE ABUTMENT ;
    PORT
      LAYER M4 ;
      RECT 46.906 21.648 46.930 21.672 ;
    END
  END rd_out_B[45]
  PIN rd_out_A[46]
    DIRECTION OUTPUT ;
    USE SIGNAL ;
    SHAPE ABUTMENT ;
    PORT
      LAYER M4 ;
      RECT 0.000 21.840 0.024 21.864 ;
    END
  END rd_out_A[46]
  PIN rd_out_B[46]
    DIRECTION OUTPUT ;
    USE SIGNAL ;
    SHAPE ABUTMENT ;
    PORT
      LAYER M4 ;
      RECT 46.906 21.840 46.930 21.864 ;
    END
  END rd_out_B[46]
  PIN rd_out_A[47]
    DIRECTION OUTPUT ;
    USE SIGNAL ;
    SHAPE ABUTMENT ;
    PORT
      LAYER M4 ;
      RECT 0.000 22.032 0.024 22.056 ;
    END
  END rd_out_A[47]
  PIN rd_out_B[47]
    DIRECTION OUTPUT ;
    USE SIGNAL ;
    SHAPE ABUTMENT ;
    PORT
      LAYER M4 ;
      RECT 46.906 22.032 46.930 22.056 ;
    END
  END rd_out_B[47]
  PIN rd_out_A[48]
    DIRECTION OUTPUT ;
    USE SIGNAL ;
    SHAPE ABUTMENT ;
    PORT
      LAYER M4 ;
      RECT 0.000 22.224 0.024 22.248 ;
    END
  END rd_out_A[48]
  PIN rd_out_B[48]
    DIRECTION OUTPUT ;
    USE SIGNAL ;
    SHAPE ABUTMENT ;
    PORT
      LAYER M4 ;
      RECT 46.906 22.224 46.930 22.248 ;
    END
  END rd_out_B[48]
  PIN rd_out_A[49]
    DIRECTION OUTPUT ;
    USE SIGNAL ;
    SHAPE ABUTMENT ;
    PORT
      LAYER M4 ;
      RECT 0.000 22.416 0.024 22.440 ;
    END
  END rd_out_A[49]
  PIN rd_out_B[49]
    DIRECTION OUTPUT ;
    USE SIGNAL ;
    SHAPE ABUTMENT ;
    PORT
      LAYER M4 ;
      RECT 46.906 22.416 46.930 22.440 ;
    END
  END rd_out_B[49]
  PIN rd_out_A[50]
    DIRECTION OUTPUT ;
    USE SIGNAL ;
    SHAPE ABUTMENT ;
    PORT
      LAYER M4 ;
      RECT 0.000 22.608 0.024 22.632 ;
    END
  END rd_out_A[50]
  PIN rd_out_B[50]
    DIRECTION OUTPUT ;
    USE SIGNAL ;
    SHAPE ABUTMENT ;
    PORT
      LAYER M4 ;
      RECT 46.906 22.608 46.930 22.632 ;
    END
  END rd_out_B[50]
  PIN rd_out_A[51]
    DIRECTION OUTPUT ;
    USE SIGNAL ;
    SHAPE ABUTMENT ;
    PORT
      LAYER M4 ;
      RECT 0.000 22.800 0.024 22.824 ;
    END
  END rd_out_A[51]
  PIN rd_out_B[51]
    DIRECTION OUTPUT ;
    USE SIGNAL ;
    SHAPE ABUTMENT ;
    PORT
      LAYER M4 ;
      RECT 46.906 22.800 46.930 22.824 ;
    END
  END rd_out_B[51]
  PIN rd_out_A[52]
    DIRECTION OUTPUT ;
    USE SIGNAL ;
    SHAPE ABUTMENT ;
    PORT
      LAYER M4 ;
      RECT 0.000 22.992 0.024 23.016 ;
    END
  END rd_out_A[52]
  PIN rd_out_B[52]
    DIRECTION OUTPUT ;
    USE SIGNAL ;
    SHAPE ABUTMENT ;
    PORT
      LAYER M4 ;
      RECT 46.906 22.992 46.930 23.016 ;
    END
  END rd_out_B[52]
  PIN rd_out_A[53]
    DIRECTION OUTPUT ;
    USE SIGNAL ;
    SHAPE ABUTMENT ;
    PORT
      LAYER M4 ;
      RECT 0.000 23.184 0.024 23.208 ;
    END
  END rd_out_A[53]
  PIN rd_out_B[53]
    DIRECTION OUTPUT ;
    USE SIGNAL ;
    SHAPE ABUTMENT ;
    PORT
      LAYER M4 ;
      RECT 46.906 23.184 46.930 23.208 ;
    END
  END rd_out_B[53]
  PIN rd_out_A[54]
    DIRECTION OUTPUT ;
    USE SIGNAL ;
    SHAPE ABUTMENT ;
    PORT
      LAYER M4 ;
      RECT 0.000 23.376 0.024 23.400 ;
    END
  END rd_out_A[54]
  PIN rd_out_B[54]
    DIRECTION OUTPUT ;
    USE SIGNAL ;
    SHAPE ABUTMENT ;
    PORT
      LAYER M4 ;
      RECT 46.906 23.376 46.930 23.400 ;
    END
  END rd_out_B[54]
  PIN rd_out_A[55]
    DIRECTION OUTPUT ;
    USE SIGNAL ;
    SHAPE ABUTMENT ;
    PORT
      LAYER M4 ;
      RECT 0.000 23.568 0.024 23.592 ;
    END
  END rd_out_A[55]
  PIN rd_out_B[55]
    DIRECTION OUTPUT ;
    USE SIGNAL ;
    SHAPE ABUTMENT ;
    PORT
      LAYER M4 ;
      RECT 46.906 23.568 46.930 23.592 ;
    END
  END rd_out_B[55]
  PIN rd_out_A[56]
    DIRECTION OUTPUT ;
    USE SIGNAL ;
    SHAPE ABUTMENT ;
    PORT
      LAYER M4 ;
      RECT 0.000 23.760 0.024 23.784 ;
    END
  END rd_out_A[56]
  PIN rd_out_B[56]
    DIRECTION OUTPUT ;
    USE SIGNAL ;
    SHAPE ABUTMENT ;
    PORT
      LAYER M4 ;
      RECT 46.906 23.760 46.930 23.784 ;
    END
  END rd_out_B[56]
  PIN rd_out_A[57]
    DIRECTION OUTPUT ;
    USE SIGNAL ;
    SHAPE ABUTMENT ;
    PORT
      LAYER M4 ;
      RECT 0.000 23.952 0.024 23.976 ;
    END
  END rd_out_A[57]
  PIN rd_out_B[57]
    DIRECTION OUTPUT ;
    USE SIGNAL ;
    SHAPE ABUTMENT ;
    PORT
      LAYER M4 ;
      RECT 46.906 23.952 46.930 23.976 ;
    END
  END rd_out_B[57]
  PIN rd_out_A[58]
    DIRECTION OUTPUT ;
    USE SIGNAL ;
    SHAPE ABUTMENT ;
    PORT
      LAYER M4 ;
      RECT 0.000 24.144 0.024 24.168 ;
    END
  END rd_out_A[58]
  PIN rd_out_B[58]
    DIRECTION OUTPUT ;
    USE SIGNAL ;
    SHAPE ABUTMENT ;
    PORT
      LAYER M4 ;
      RECT 46.906 24.144 46.930 24.168 ;
    END
  END rd_out_B[58]
  PIN rd_out_A[59]
    DIRECTION OUTPUT ;
    USE SIGNAL ;
    SHAPE ABUTMENT ;
    PORT
      LAYER M4 ;
      RECT 0.000 24.336 0.024 24.360 ;
    END
  END rd_out_A[59]
  PIN rd_out_B[59]
    DIRECTION OUTPUT ;
    USE SIGNAL ;
    SHAPE ABUTMENT ;
    PORT
      LAYER M4 ;
      RECT 46.906 24.336 46.930 24.360 ;
    END
  END rd_out_B[59]
  PIN rd_out_A[60]
    DIRECTION OUTPUT ;
    USE SIGNAL ;
    SHAPE ABUTMENT ;
    PORT
      LAYER M4 ;
      RECT 0.000 24.528 0.024 24.552 ;
    END
  END rd_out_A[60]
  PIN rd_out_B[60]
    DIRECTION OUTPUT ;
    USE SIGNAL ;
    SHAPE ABUTMENT ;
    PORT
      LAYER M4 ;
      RECT 46.906 24.528 46.930 24.552 ;
    END
  END rd_out_B[60]
  PIN rd_out_A[61]
    DIRECTION OUTPUT ;
    USE SIGNAL ;
    SHAPE ABUTMENT ;
    PORT
      LAYER M4 ;
      RECT 0.000 24.720 0.024 24.744 ;
    END
  END rd_out_A[61]
  PIN rd_out_B[61]
    DIRECTION OUTPUT ;
    USE SIGNAL ;
    SHAPE ABUTMENT ;
    PORT
      LAYER M4 ;
      RECT 46.906 24.720 46.930 24.744 ;
    END
  END rd_out_B[61]
  PIN rd_out_A[62]
    DIRECTION OUTPUT ;
    USE SIGNAL ;
    SHAPE ABUTMENT ;
    PORT
      LAYER M4 ;
      RECT 0.000 24.912 0.024 24.936 ;
    END
  END rd_out_A[62]
  PIN rd_out_B[62]
    DIRECTION OUTPUT ;
    USE SIGNAL ;
    SHAPE ABUTMENT ;
    PORT
      LAYER M4 ;
      RECT 46.906 24.912 46.930 24.936 ;
    END
  END rd_out_B[62]
  PIN rd_out_A[63]
    DIRECTION OUTPUT ;
    USE SIGNAL ;
    SHAPE ABUTMENT ;
    PORT
      LAYER M4 ;
      RECT 0.000 25.104 0.024 25.128 ;
    END
  END rd_out_A[63]
  PIN rd_out_B[63]
    DIRECTION OUTPUT ;
    USE SIGNAL ;
    SHAPE ABUTMENT ;
    PORT
      LAYER M4 ;
      RECT 46.906 25.104 46.930 25.128 ;
    END
  END rd_out_B[63]
  PIN wd_in_A[0]
    DIRECTION INPUT ;
    USE SIGNAL ;
    SHAPE ABUTMENT ;
    PORT
      LAYER M4 ;
      RECT 0.000 25.968 0.024 25.992 ;
    END
  END wd_in_A[0]
  PIN wd_in_B[0]
    DIRECTION INPUT ;
    USE SIGNAL ;
    SHAPE ABUTMENT ;
    PORT
      LAYER M4 ;
      RECT 46.906 25.968 46.930 25.992 ;
    END
  END wd_in_B[0]
  PIN wd_in_A[1]
    DIRECTION INPUT ;
    USE SIGNAL ;
    SHAPE ABUTMENT ;
    PORT
      LAYER M4 ;
      RECT 0.000 26.160 0.024 26.184 ;
    END
  END wd_in_A[1]
  PIN wd_in_B[1]
    DIRECTION INPUT ;
    USE SIGNAL ;
    SHAPE ABUTMENT ;
    PORT
      LAYER M4 ;
      RECT 46.906 26.160 46.930 26.184 ;
    END
  END wd_in_B[1]
  PIN wd_in_A[2]
    DIRECTION INPUT ;
    USE SIGNAL ;
    SHAPE ABUTMENT ;
    PORT
      LAYER M4 ;
      RECT 0.000 26.352 0.024 26.376 ;
    END
  END wd_in_A[2]
  PIN wd_in_B[2]
    DIRECTION INPUT ;
    USE SIGNAL ;
    SHAPE ABUTMENT ;
    PORT
      LAYER M4 ;
      RECT 46.906 26.352 46.930 26.376 ;
    END
  END wd_in_B[2]
  PIN wd_in_A[3]
    DIRECTION INPUT ;
    USE SIGNAL ;
    SHAPE ABUTMENT ;
    PORT
      LAYER M4 ;
      RECT 0.000 26.544 0.024 26.568 ;
    END
  END wd_in_A[3]
  PIN wd_in_B[3]
    DIRECTION INPUT ;
    USE SIGNAL ;
    SHAPE ABUTMENT ;
    PORT
      LAYER M4 ;
      RECT 46.906 26.544 46.930 26.568 ;
    END
  END wd_in_B[3]
  PIN wd_in_A[4]
    DIRECTION INPUT ;
    USE SIGNAL ;
    SHAPE ABUTMENT ;
    PORT
      LAYER M4 ;
      RECT 0.000 26.736 0.024 26.760 ;
    END
  END wd_in_A[4]
  PIN wd_in_B[4]
    DIRECTION INPUT ;
    USE SIGNAL ;
    SHAPE ABUTMENT ;
    PORT
      LAYER M4 ;
      RECT 46.906 26.736 46.930 26.760 ;
    END
  END wd_in_B[4]
  PIN wd_in_A[5]
    DIRECTION INPUT ;
    USE SIGNAL ;
    SHAPE ABUTMENT ;
    PORT
      LAYER M4 ;
      RECT 0.000 26.928 0.024 26.952 ;
    END
  END wd_in_A[5]
  PIN wd_in_B[5]
    DIRECTION INPUT ;
    USE SIGNAL ;
    SHAPE ABUTMENT ;
    PORT
      LAYER M4 ;
      RECT 46.906 26.928 46.930 26.952 ;
    END
  END wd_in_B[5]
  PIN wd_in_A[6]
    DIRECTION INPUT ;
    USE SIGNAL ;
    SHAPE ABUTMENT ;
    PORT
      LAYER M4 ;
      RECT 0.000 27.120 0.024 27.144 ;
    END
  END wd_in_A[6]
  PIN wd_in_B[6]
    DIRECTION INPUT ;
    USE SIGNAL ;
    SHAPE ABUTMENT ;
    PORT
      LAYER M4 ;
      RECT 46.906 27.120 46.930 27.144 ;
    END
  END wd_in_B[6]
  PIN wd_in_A[7]
    DIRECTION INPUT ;
    USE SIGNAL ;
    SHAPE ABUTMENT ;
    PORT
      LAYER M4 ;
      RECT 0.000 27.312 0.024 27.336 ;
    END
  END wd_in_A[7]
  PIN wd_in_B[7]
    DIRECTION INPUT ;
    USE SIGNAL ;
    SHAPE ABUTMENT ;
    PORT
      LAYER M4 ;
      RECT 46.906 27.312 46.930 27.336 ;
    END
  END wd_in_B[7]
  PIN wd_in_A[8]
    DIRECTION INPUT ;
    USE SIGNAL ;
    SHAPE ABUTMENT ;
    PORT
      LAYER M4 ;
      RECT 0.000 27.504 0.024 27.528 ;
    END
  END wd_in_A[8]
  PIN wd_in_B[8]
    DIRECTION INPUT ;
    USE SIGNAL ;
    SHAPE ABUTMENT ;
    PORT
      LAYER M4 ;
      RECT 46.906 27.504 46.930 27.528 ;
    END
  END wd_in_B[8]
  PIN wd_in_A[9]
    DIRECTION INPUT ;
    USE SIGNAL ;
    SHAPE ABUTMENT ;
    PORT
      LAYER M4 ;
      RECT 0.000 27.696 0.024 27.720 ;
    END
  END wd_in_A[9]
  PIN wd_in_B[9]
    DIRECTION INPUT ;
    USE SIGNAL ;
    SHAPE ABUTMENT ;
    PORT
      LAYER M4 ;
      RECT 46.906 27.696 46.930 27.720 ;
    END
  END wd_in_B[9]
  PIN wd_in_A[10]
    DIRECTION INPUT ;
    USE SIGNAL ;
    SHAPE ABUTMENT ;
    PORT
      LAYER M4 ;
      RECT 0.000 27.888 0.024 27.912 ;
    END
  END wd_in_A[10]
  PIN wd_in_B[10]
    DIRECTION INPUT ;
    USE SIGNAL ;
    SHAPE ABUTMENT ;
    PORT
      LAYER M4 ;
      RECT 46.906 27.888 46.930 27.912 ;
    END
  END wd_in_B[10]
  PIN wd_in_A[11]
    DIRECTION INPUT ;
    USE SIGNAL ;
    SHAPE ABUTMENT ;
    PORT
      LAYER M4 ;
      RECT 0.000 28.080 0.024 28.104 ;
    END
  END wd_in_A[11]
  PIN wd_in_B[11]
    DIRECTION INPUT ;
    USE SIGNAL ;
    SHAPE ABUTMENT ;
    PORT
      LAYER M4 ;
      RECT 46.906 28.080 46.930 28.104 ;
    END
  END wd_in_B[11]
  PIN wd_in_A[12]
    DIRECTION INPUT ;
    USE SIGNAL ;
    SHAPE ABUTMENT ;
    PORT
      LAYER M4 ;
      RECT 0.000 28.272 0.024 28.296 ;
    END
  END wd_in_A[12]
  PIN wd_in_B[12]
    DIRECTION INPUT ;
    USE SIGNAL ;
    SHAPE ABUTMENT ;
    PORT
      LAYER M4 ;
      RECT 46.906 28.272 46.930 28.296 ;
    END
  END wd_in_B[12]
  PIN wd_in_A[13]
    DIRECTION INPUT ;
    USE SIGNAL ;
    SHAPE ABUTMENT ;
    PORT
      LAYER M4 ;
      RECT 0.000 28.464 0.024 28.488 ;
    END
  END wd_in_A[13]
  PIN wd_in_B[13]
    DIRECTION INPUT ;
    USE SIGNAL ;
    SHAPE ABUTMENT ;
    PORT
      LAYER M4 ;
      RECT 46.906 28.464 46.930 28.488 ;
    END
  END wd_in_B[13]
  PIN wd_in_A[14]
    DIRECTION INPUT ;
    USE SIGNAL ;
    SHAPE ABUTMENT ;
    PORT
      LAYER M4 ;
      RECT 0.000 28.656 0.024 28.680 ;
    END
  END wd_in_A[14]
  PIN wd_in_B[14]
    DIRECTION INPUT ;
    USE SIGNAL ;
    SHAPE ABUTMENT ;
    PORT
      LAYER M4 ;
      RECT 46.906 28.656 46.930 28.680 ;
    END
  END wd_in_B[14]
  PIN wd_in_A[15]
    DIRECTION INPUT ;
    USE SIGNAL ;
    SHAPE ABUTMENT ;
    PORT
      LAYER M4 ;
      RECT 0.000 28.848 0.024 28.872 ;
    END
  END wd_in_A[15]
  PIN wd_in_B[15]
    DIRECTION INPUT ;
    USE SIGNAL ;
    SHAPE ABUTMENT ;
    PORT
      LAYER M4 ;
      RECT 46.906 28.848 46.930 28.872 ;
    END
  END wd_in_B[15]
  PIN wd_in_A[16]
    DIRECTION INPUT ;
    USE SIGNAL ;
    SHAPE ABUTMENT ;
    PORT
      LAYER M4 ;
      RECT 0.000 29.040 0.024 29.064 ;
    END
  END wd_in_A[16]
  PIN wd_in_B[16]
    DIRECTION INPUT ;
    USE SIGNAL ;
    SHAPE ABUTMENT ;
    PORT
      LAYER M4 ;
      RECT 46.906 29.040 46.930 29.064 ;
    END
  END wd_in_B[16]
  PIN wd_in_A[17]
    DIRECTION INPUT ;
    USE SIGNAL ;
    SHAPE ABUTMENT ;
    PORT
      LAYER M4 ;
      RECT 0.000 29.232 0.024 29.256 ;
    END
  END wd_in_A[17]
  PIN wd_in_B[17]
    DIRECTION INPUT ;
    USE SIGNAL ;
    SHAPE ABUTMENT ;
    PORT
      LAYER M4 ;
      RECT 46.906 29.232 46.930 29.256 ;
    END
  END wd_in_B[17]
  PIN wd_in_A[18]
    DIRECTION INPUT ;
    USE SIGNAL ;
    SHAPE ABUTMENT ;
    PORT
      LAYER M4 ;
      RECT 0.000 29.424 0.024 29.448 ;
    END
  END wd_in_A[18]
  PIN wd_in_B[18]
    DIRECTION INPUT ;
    USE SIGNAL ;
    SHAPE ABUTMENT ;
    PORT
      LAYER M4 ;
      RECT 46.906 29.424 46.930 29.448 ;
    END
  END wd_in_B[18]
  PIN wd_in_A[19]
    DIRECTION INPUT ;
    USE SIGNAL ;
    SHAPE ABUTMENT ;
    PORT
      LAYER M4 ;
      RECT 0.000 29.616 0.024 29.640 ;
    END
  END wd_in_A[19]
  PIN wd_in_B[19]
    DIRECTION INPUT ;
    USE SIGNAL ;
    SHAPE ABUTMENT ;
    PORT
      LAYER M4 ;
      RECT 46.906 29.616 46.930 29.640 ;
    END
  END wd_in_B[19]
  PIN wd_in_A[20]
    DIRECTION INPUT ;
    USE SIGNAL ;
    SHAPE ABUTMENT ;
    PORT
      LAYER M4 ;
      RECT 0.000 29.808 0.024 29.832 ;
    END
  END wd_in_A[20]
  PIN wd_in_B[20]
    DIRECTION INPUT ;
    USE SIGNAL ;
    SHAPE ABUTMENT ;
    PORT
      LAYER M4 ;
      RECT 46.906 29.808 46.930 29.832 ;
    END
  END wd_in_B[20]
  PIN wd_in_A[21]
    DIRECTION INPUT ;
    USE SIGNAL ;
    SHAPE ABUTMENT ;
    PORT
      LAYER M4 ;
      RECT 0.000 30.000 0.024 30.024 ;
    END
  END wd_in_A[21]
  PIN wd_in_B[21]
    DIRECTION INPUT ;
    USE SIGNAL ;
    SHAPE ABUTMENT ;
    PORT
      LAYER M4 ;
      RECT 46.906 30.000 46.930 30.024 ;
    END
  END wd_in_B[21]
  PIN wd_in_A[22]
    DIRECTION INPUT ;
    USE SIGNAL ;
    SHAPE ABUTMENT ;
    PORT
      LAYER M4 ;
      RECT 0.000 30.192 0.024 30.216 ;
    END
  END wd_in_A[22]
  PIN wd_in_B[22]
    DIRECTION INPUT ;
    USE SIGNAL ;
    SHAPE ABUTMENT ;
    PORT
      LAYER M4 ;
      RECT 46.906 30.192 46.930 30.216 ;
    END
  END wd_in_B[22]
  PIN wd_in_A[23]
    DIRECTION INPUT ;
    USE SIGNAL ;
    SHAPE ABUTMENT ;
    PORT
      LAYER M4 ;
      RECT 0.000 30.384 0.024 30.408 ;
    END
  END wd_in_A[23]
  PIN wd_in_B[23]
    DIRECTION INPUT ;
    USE SIGNAL ;
    SHAPE ABUTMENT ;
    PORT
      LAYER M4 ;
      RECT 46.906 30.384 46.930 30.408 ;
    END
  END wd_in_B[23]
  PIN wd_in_A[24]
    DIRECTION INPUT ;
    USE SIGNAL ;
    SHAPE ABUTMENT ;
    PORT
      LAYER M4 ;
      RECT 0.000 30.576 0.024 30.600 ;
    END
  END wd_in_A[24]
  PIN wd_in_B[24]
    DIRECTION INPUT ;
    USE SIGNAL ;
    SHAPE ABUTMENT ;
    PORT
      LAYER M4 ;
      RECT 46.906 30.576 46.930 30.600 ;
    END
  END wd_in_B[24]
  PIN wd_in_A[25]
    DIRECTION INPUT ;
    USE SIGNAL ;
    SHAPE ABUTMENT ;
    PORT
      LAYER M4 ;
      RECT 0.000 30.768 0.024 30.792 ;
    END
  END wd_in_A[25]
  PIN wd_in_B[25]
    DIRECTION INPUT ;
    USE SIGNAL ;
    SHAPE ABUTMENT ;
    PORT
      LAYER M4 ;
      RECT 46.906 30.768 46.930 30.792 ;
    END
  END wd_in_B[25]
  PIN wd_in_A[26]
    DIRECTION INPUT ;
    USE SIGNAL ;
    SHAPE ABUTMENT ;
    PORT
      LAYER M4 ;
      RECT 0.000 30.960 0.024 30.984 ;
    END
  END wd_in_A[26]
  PIN wd_in_B[26]
    DIRECTION INPUT ;
    USE SIGNAL ;
    SHAPE ABUTMENT ;
    PORT
      LAYER M4 ;
      RECT 46.906 30.960 46.930 30.984 ;
    END
  END wd_in_B[26]
  PIN wd_in_A[27]
    DIRECTION INPUT ;
    USE SIGNAL ;
    SHAPE ABUTMENT ;
    PORT
      LAYER M4 ;
      RECT 0.000 31.152 0.024 31.176 ;
    END
  END wd_in_A[27]
  PIN wd_in_B[27]
    DIRECTION INPUT ;
    USE SIGNAL ;
    SHAPE ABUTMENT ;
    PORT
      LAYER M4 ;
      RECT 46.906 31.152 46.930 31.176 ;
    END
  END wd_in_B[27]
  PIN wd_in_A[28]
    DIRECTION INPUT ;
    USE SIGNAL ;
    SHAPE ABUTMENT ;
    PORT
      LAYER M4 ;
      RECT 0.000 31.344 0.024 31.368 ;
    END
  END wd_in_A[28]
  PIN wd_in_B[28]
    DIRECTION INPUT ;
    USE SIGNAL ;
    SHAPE ABUTMENT ;
    PORT
      LAYER M4 ;
      RECT 46.906 31.344 46.930 31.368 ;
    END
  END wd_in_B[28]
  PIN wd_in_A[29]
    DIRECTION INPUT ;
    USE SIGNAL ;
    SHAPE ABUTMENT ;
    PORT
      LAYER M4 ;
      RECT 0.000 31.536 0.024 31.560 ;
    END
  END wd_in_A[29]
  PIN wd_in_B[29]
    DIRECTION INPUT ;
    USE SIGNAL ;
    SHAPE ABUTMENT ;
    PORT
      LAYER M4 ;
      RECT 46.906 31.536 46.930 31.560 ;
    END
  END wd_in_B[29]
  PIN wd_in_A[30]
    DIRECTION INPUT ;
    USE SIGNAL ;
    SHAPE ABUTMENT ;
    PORT
      LAYER M4 ;
      RECT 0.000 31.728 0.024 31.752 ;
    END
  END wd_in_A[30]
  PIN wd_in_B[30]
    DIRECTION INPUT ;
    USE SIGNAL ;
    SHAPE ABUTMENT ;
    PORT
      LAYER M4 ;
      RECT 46.906 31.728 46.930 31.752 ;
    END
  END wd_in_B[30]
  PIN wd_in_A[31]
    DIRECTION INPUT ;
    USE SIGNAL ;
    SHAPE ABUTMENT ;
    PORT
      LAYER M4 ;
      RECT 0.000 31.920 0.024 31.944 ;
    END
  END wd_in_A[31]
  PIN wd_in_B[31]
    DIRECTION INPUT ;
    USE SIGNAL ;
    SHAPE ABUTMENT ;
    PORT
      LAYER M4 ;
      RECT 46.906 31.920 46.930 31.944 ;
    END
  END wd_in_B[31]
  PIN wd_in_A[32]
    DIRECTION INPUT ;
    USE SIGNAL ;
    SHAPE ABUTMENT ;
    PORT
      LAYER M4 ;
      RECT 0.000 32.112 0.024 32.136 ;
    END
  END wd_in_A[32]
  PIN wd_in_B[32]
    DIRECTION INPUT ;
    USE SIGNAL ;
    SHAPE ABUTMENT ;
    PORT
      LAYER M4 ;
      RECT 46.906 32.112 46.930 32.136 ;
    END
  END wd_in_B[32]
  PIN wd_in_A[33]
    DIRECTION INPUT ;
    USE SIGNAL ;
    SHAPE ABUTMENT ;
    PORT
      LAYER M4 ;
      RECT 0.000 32.304 0.024 32.328 ;
    END
  END wd_in_A[33]
  PIN wd_in_B[33]
    DIRECTION INPUT ;
    USE SIGNAL ;
    SHAPE ABUTMENT ;
    PORT
      LAYER M4 ;
      RECT 46.906 32.304 46.930 32.328 ;
    END
  END wd_in_B[33]
  PIN wd_in_A[34]
    DIRECTION INPUT ;
    USE SIGNAL ;
    SHAPE ABUTMENT ;
    PORT
      LAYER M4 ;
      RECT 0.000 32.496 0.024 32.520 ;
    END
  END wd_in_A[34]
  PIN wd_in_B[34]
    DIRECTION INPUT ;
    USE SIGNAL ;
    SHAPE ABUTMENT ;
    PORT
      LAYER M4 ;
      RECT 46.906 32.496 46.930 32.520 ;
    END
  END wd_in_B[34]
  PIN wd_in_A[35]
    DIRECTION INPUT ;
    USE SIGNAL ;
    SHAPE ABUTMENT ;
    PORT
      LAYER M4 ;
      RECT 0.000 32.688 0.024 32.712 ;
    END
  END wd_in_A[35]
  PIN wd_in_B[35]
    DIRECTION INPUT ;
    USE SIGNAL ;
    SHAPE ABUTMENT ;
    PORT
      LAYER M4 ;
      RECT 46.906 32.688 46.930 32.712 ;
    END
  END wd_in_B[35]
  PIN wd_in_A[36]
    DIRECTION INPUT ;
    USE SIGNAL ;
    SHAPE ABUTMENT ;
    PORT
      LAYER M4 ;
      RECT 0.000 32.880 0.024 32.904 ;
    END
  END wd_in_A[36]
  PIN wd_in_B[36]
    DIRECTION INPUT ;
    USE SIGNAL ;
    SHAPE ABUTMENT ;
    PORT
      LAYER M4 ;
      RECT 46.906 32.880 46.930 32.904 ;
    END
  END wd_in_B[36]
  PIN wd_in_A[37]
    DIRECTION INPUT ;
    USE SIGNAL ;
    SHAPE ABUTMENT ;
    PORT
      LAYER M4 ;
      RECT 0.000 33.072 0.024 33.096 ;
    END
  END wd_in_A[37]
  PIN wd_in_B[37]
    DIRECTION INPUT ;
    USE SIGNAL ;
    SHAPE ABUTMENT ;
    PORT
      LAYER M4 ;
      RECT 46.906 33.072 46.930 33.096 ;
    END
  END wd_in_B[37]
  PIN wd_in_A[38]
    DIRECTION INPUT ;
    USE SIGNAL ;
    SHAPE ABUTMENT ;
    PORT
      LAYER M4 ;
      RECT 0.000 33.264 0.024 33.288 ;
    END
  END wd_in_A[38]
  PIN wd_in_B[38]
    DIRECTION INPUT ;
    USE SIGNAL ;
    SHAPE ABUTMENT ;
    PORT
      LAYER M4 ;
      RECT 46.906 33.264 46.930 33.288 ;
    END
  END wd_in_B[38]
  PIN wd_in_A[39]
    DIRECTION INPUT ;
    USE SIGNAL ;
    SHAPE ABUTMENT ;
    PORT
      LAYER M4 ;
      RECT 0.000 33.456 0.024 33.480 ;
    END
  END wd_in_A[39]
  PIN wd_in_B[39]
    DIRECTION INPUT ;
    USE SIGNAL ;
    SHAPE ABUTMENT ;
    PORT
      LAYER M4 ;
      RECT 46.906 33.456 46.930 33.480 ;
    END
  END wd_in_B[39]
  PIN wd_in_A[40]
    DIRECTION INPUT ;
    USE SIGNAL ;
    SHAPE ABUTMENT ;
    PORT
      LAYER M4 ;
      RECT 0.000 33.648 0.024 33.672 ;
    END
  END wd_in_A[40]
  PIN wd_in_B[40]
    DIRECTION INPUT ;
    USE SIGNAL ;
    SHAPE ABUTMENT ;
    PORT
      LAYER M4 ;
      RECT 46.906 33.648 46.930 33.672 ;
    END
  END wd_in_B[40]
  PIN wd_in_A[41]
    DIRECTION INPUT ;
    USE SIGNAL ;
    SHAPE ABUTMENT ;
    PORT
      LAYER M4 ;
      RECT 0.000 33.840 0.024 33.864 ;
    END
  END wd_in_A[41]
  PIN wd_in_B[41]
    DIRECTION INPUT ;
    USE SIGNAL ;
    SHAPE ABUTMENT ;
    PORT
      LAYER M4 ;
      RECT 46.906 33.840 46.930 33.864 ;
    END
  END wd_in_B[41]
  PIN wd_in_A[42]
    DIRECTION INPUT ;
    USE SIGNAL ;
    SHAPE ABUTMENT ;
    PORT
      LAYER M4 ;
      RECT 0.000 34.032 0.024 34.056 ;
    END
  END wd_in_A[42]
  PIN wd_in_B[42]
    DIRECTION INPUT ;
    USE SIGNAL ;
    SHAPE ABUTMENT ;
    PORT
      LAYER M4 ;
      RECT 46.906 34.032 46.930 34.056 ;
    END
  END wd_in_B[42]
  PIN wd_in_A[43]
    DIRECTION INPUT ;
    USE SIGNAL ;
    SHAPE ABUTMENT ;
    PORT
      LAYER M4 ;
      RECT 0.000 34.224 0.024 34.248 ;
    END
  END wd_in_A[43]
  PIN wd_in_B[43]
    DIRECTION INPUT ;
    USE SIGNAL ;
    SHAPE ABUTMENT ;
    PORT
      LAYER M4 ;
      RECT 46.906 34.224 46.930 34.248 ;
    END
  END wd_in_B[43]
  PIN wd_in_A[44]
    DIRECTION INPUT ;
    USE SIGNAL ;
    SHAPE ABUTMENT ;
    PORT
      LAYER M4 ;
      RECT 0.000 34.416 0.024 34.440 ;
    END
  END wd_in_A[44]
  PIN wd_in_B[44]
    DIRECTION INPUT ;
    USE SIGNAL ;
    SHAPE ABUTMENT ;
    PORT
      LAYER M4 ;
      RECT 46.906 34.416 46.930 34.440 ;
    END
  END wd_in_B[44]
  PIN wd_in_A[45]
    DIRECTION INPUT ;
    USE SIGNAL ;
    SHAPE ABUTMENT ;
    PORT
      LAYER M4 ;
      RECT 0.000 34.608 0.024 34.632 ;
    END
  END wd_in_A[45]
  PIN wd_in_B[45]
    DIRECTION INPUT ;
    USE SIGNAL ;
    SHAPE ABUTMENT ;
    PORT
      LAYER M4 ;
      RECT 46.906 34.608 46.930 34.632 ;
    END
  END wd_in_B[45]
  PIN wd_in_A[46]
    DIRECTION INPUT ;
    USE SIGNAL ;
    SHAPE ABUTMENT ;
    PORT
      LAYER M4 ;
      RECT 0.000 34.800 0.024 34.824 ;
    END
  END wd_in_A[46]
  PIN wd_in_B[46]
    DIRECTION INPUT ;
    USE SIGNAL ;
    SHAPE ABUTMENT ;
    PORT
      LAYER M4 ;
      RECT 46.906 34.800 46.930 34.824 ;
    END
  END wd_in_B[46]
  PIN wd_in_A[47]
    DIRECTION INPUT ;
    USE SIGNAL ;
    SHAPE ABUTMENT ;
    PORT
      LAYER M4 ;
      RECT 0.000 34.992 0.024 35.016 ;
    END
  END wd_in_A[47]
  PIN wd_in_B[47]
    DIRECTION INPUT ;
    USE SIGNAL ;
    SHAPE ABUTMENT ;
    PORT
      LAYER M4 ;
      RECT 46.906 34.992 46.930 35.016 ;
    END
  END wd_in_B[47]
  PIN wd_in_A[48]
    DIRECTION INPUT ;
    USE SIGNAL ;
    SHAPE ABUTMENT ;
    PORT
      LAYER M4 ;
      RECT 0.000 35.184 0.024 35.208 ;
    END
  END wd_in_A[48]
  PIN wd_in_B[48]
    DIRECTION INPUT ;
    USE SIGNAL ;
    SHAPE ABUTMENT ;
    PORT
      LAYER M4 ;
      RECT 46.906 35.184 46.930 35.208 ;
    END
  END wd_in_B[48]
  PIN wd_in_A[49]
    DIRECTION INPUT ;
    USE SIGNAL ;
    SHAPE ABUTMENT ;
    PORT
      LAYER M4 ;
      RECT 0.000 35.376 0.024 35.400 ;
    END
  END wd_in_A[49]
  PIN wd_in_B[49]
    DIRECTION INPUT ;
    USE SIGNAL ;
    SHAPE ABUTMENT ;
    PORT
      LAYER M4 ;
      RECT 46.906 35.376 46.930 35.400 ;
    END
  END wd_in_B[49]
  PIN wd_in_A[50]
    DIRECTION INPUT ;
    USE SIGNAL ;
    SHAPE ABUTMENT ;
    PORT
      LAYER M4 ;
      RECT 0.000 35.568 0.024 35.592 ;
    END
  END wd_in_A[50]
  PIN wd_in_B[50]
    DIRECTION INPUT ;
    USE SIGNAL ;
    SHAPE ABUTMENT ;
    PORT
      LAYER M4 ;
      RECT 46.906 35.568 46.930 35.592 ;
    END
  END wd_in_B[50]
  PIN wd_in_A[51]
    DIRECTION INPUT ;
    USE SIGNAL ;
    SHAPE ABUTMENT ;
    PORT
      LAYER M4 ;
      RECT 0.000 35.760 0.024 35.784 ;
    END
  END wd_in_A[51]
  PIN wd_in_B[51]
    DIRECTION INPUT ;
    USE SIGNAL ;
    SHAPE ABUTMENT ;
    PORT
      LAYER M4 ;
      RECT 46.906 35.760 46.930 35.784 ;
    END
  END wd_in_B[51]
  PIN wd_in_A[52]
    DIRECTION INPUT ;
    USE SIGNAL ;
    SHAPE ABUTMENT ;
    PORT
      LAYER M4 ;
      RECT 0.000 35.952 0.024 35.976 ;
    END
  END wd_in_A[52]
  PIN wd_in_B[52]
    DIRECTION INPUT ;
    USE SIGNAL ;
    SHAPE ABUTMENT ;
    PORT
      LAYER M4 ;
      RECT 46.906 35.952 46.930 35.976 ;
    END
  END wd_in_B[52]
  PIN wd_in_A[53]
    DIRECTION INPUT ;
    USE SIGNAL ;
    SHAPE ABUTMENT ;
    PORT
      LAYER M4 ;
      RECT 0.000 36.144 0.024 36.168 ;
    END
  END wd_in_A[53]
  PIN wd_in_B[53]
    DIRECTION INPUT ;
    USE SIGNAL ;
    SHAPE ABUTMENT ;
    PORT
      LAYER M4 ;
      RECT 46.906 36.144 46.930 36.168 ;
    END
  END wd_in_B[53]
  PIN wd_in_A[54]
    DIRECTION INPUT ;
    USE SIGNAL ;
    SHAPE ABUTMENT ;
    PORT
      LAYER M4 ;
      RECT 0.000 36.336 0.024 36.360 ;
    END
  END wd_in_A[54]
  PIN wd_in_B[54]
    DIRECTION INPUT ;
    USE SIGNAL ;
    SHAPE ABUTMENT ;
    PORT
      LAYER M4 ;
      RECT 46.906 36.336 46.930 36.360 ;
    END
  END wd_in_B[54]
  PIN wd_in_A[55]
    DIRECTION INPUT ;
    USE SIGNAL ;
    SHAPE ABUTMENT ;
    PORT
      LAYER M4 ;
      RECT 0.000 36.528 0.024 36.552 ;
    END
  END wd_in_A[55]
  PIN wd_in_B[55]
    DIRECTION INPUT ;
    USE SIGNAL ;
    SHAPE ABUTMENT ;
    PORT
      LAYER M4 ;
      RECT 46.906 36.528 46.930 36.552 ;
    END
  END wd_in_B[55]
  PIN wd_in_A[56]
    DIRECTION INPUT ;
    USE SIGNAL ;
    SHAPE ABUTMENT ;
    PORT
      LAYER M4 ;
      RECT 0.000 36.720 0.024 36.744 ;
    END
  END wd_in_A[56]
  PIN wd_in_B[56]
    DIRECTION INPUT ;
    USE SIGNAL ;
    SHAPE ABUTMENT ;
    PORT
      LAYER M4 ;
      RECT 46.906 36.720 46.930 36.744 ;
    END
  END wd_in_B[56]
  PIN wd_in_A[57]
    DIRECTION INPUT ;
    USE SIGNAL ;
    SHAPE ABUTMENT ;
    PORT
      LAYER M4 ;
      RECT 0.000 36.912 0.024 36.936 ;
    END
  END wd_in_A[57]
  PIN wd_in_B[57]
    DIRECTION INPUT ;
    USE SIGNAL ;
    SHAPE ABUTMENT ;
    PORT
      LAYER M4 ;
      RECT 46.906 36.912 46.930 36.936 ;
    END
  END wd_in_B[57]
  PIN wd_in_A[58]
    DIRECTION INPUT ;
    USE SIGNAL ;
    SHAPE ABUTMENT ;
    PORT
      LAYER M4 ;
      RECT 0.000 37.104 0.024 37.128 ;
    END
  END wd_in_A[58]
  PIN wd_in_B[58]
    DIRECTION INPUT ;
    USE SIGNAL ;
    SHAPE ABUTMENT ;
    PORT
      LAYER M4 ;
      RECT 46.906 37.104 46.930 37.128 ;
    END
  END wd_in_B[58]
  PIN wd_in_A[59]
    DIRECTION INPUT ;
    USE SIGNAL ;
    SHAPE ABUTMENT ;
    PORT
      LAYER M4 ;
      RECT 0.000 37.296 0.024 37.320 ;
    END
  END wd_in_A[59]
  PIN wd_in_B[59]
    DIRECTION INPUT ;
    USE SIGNAL ;
    SHAPE ABUTMENT ;
    PORT
      LAYER M4 ;
      RECT 46.906 37.296 46.930 37.320 ;
    END
  END wd_in_B[59]
  PIN wd_in_A[60]
    DIRECTION INPUT ;
    USE SIGNAL ;
    SHAPE ABUTMENT ;
    PORT
      LAYER M4 ;
      RECT 0.000 37.488 0.024 37.512 ;
    END
  END wd_in_A[60]
  PIN wd_in_B[60]
    DIRECTION INPUT ;
    USE SIGNAL ;
    SHAPE ABUTMENT ;
    PORT
      LAYER M4 ;
      RECT 46.906 37.488 46.930 37.512 ;
    END
  END wd_in_B[60]
  PIN wd_in_A[61]
    DIRECTION INPUT ;
    USE SIGNAL ;
    SHAPE ABUTMENT ;
    PORT
      LAYER M4 ;
      RECT 0.000 37.680 0.024 37.704 ;
    END
  END wd_in_A[61]
  PIN wd_in_B[61]
    DIRECTION INPUT ;
    USE SIGNAL ;
    SHAPE ABUTMENT ;
    PORT
      LAYER M4 ;
      RECT 46.906 37.680 46.930 37.704 ;
    END
  END wd_in_B[61]
  PIN wd_in_A[62]
    DIRECTION INPUT ;
    USE SIGNAL ;
    SHAPE ABUTMENT ;
    PORT
      LAYER M4 ;
      RECT 0.000 37.872 0.024 37.896 ;
    END
  END wd_in_A[62]
  PIN wd_in_B[62]
    DIRECTION INPUT ;
    USE SIGNAL ;
    SHAPE ABUTMENT ;
    PORT
      LAYER M4 ;
      RECT 46.906 37.872 46.930 37.896 ;
    END
  END wd_in_B[62]
  PIN wd_in_A[63]
    DIRECTION INPUT ;
    USE SIGNAL ;
    SHAPE ABUTMENT ;
    PORT
      LAYER M4 ;
      RECT 0.000 38.064 0.024 38.088 ;
    END
  END wd_in_A[63]
  PIN wd_in_B[63]
    DIRECTION INPUT ;
    USE SIGNAL ;
    SHAPE ABUTMENT ;
    PORT
      LAYER M4 ;
      RECT 46.906 38.064 46.930 38.088 ;
    END
  END wd_in_B[63]
  PIN addr_in_A[0]
    DIRECTION INPUT ;
    USE SIGNAL ;
    SHAPE ABUTMENT ;
    PORT
      LAYER M4 ;
      RECT 0.000 38.928 0.024 38.952 ;
    END
  END addr_in_A[0]
  PIN addr_in_B[0]
    DIRECTION INPUT ;
    USE SIGNAL ;
    SHAPE ABUTMENT ;
    PORT
      LAYER M4 ;
      RECT 46.906 38.928 46.930 38.952 ;
    END
  END addr_in_B[0]
  PIN addr_in_A[1]
    DIRECTION INPUT ;
    USE SIGNAL ;
    SHAPE ABUTMENT ;
    PORT
      LAYER M4 ;
      RECT 0.000 39.120 0.024 39.144 ;
    END
  END addr_in_A[1]
  PIN addr_in_B[1]
    DIRECTION INPUT ;
    USE SIGNAL ;
    SHAPE ABUTMENT ;
    PORT
      LAYER M4 ;
      RECT 46.906 39.120 46.930 39.144 ;
    END
  END addr_in_B[1]
  PIN addr_in_A[2]
    DIRECTION INPUT ;
    USE SIGNAL ;
    SHAPE ABUTMENT ;
    PORT
      LAYER M4 ;
      RECT 0.000 39.312 0.024 39.336 ;
    END
  END addr_in_A[2]
  PIN addr_in_B[2]
    DIRECTION INPUT ;
    USE SIGNAL ;
    SHAPE ABUTMENT ;
    PORT
      LAYER M4 ;
      RECT 46.906 39.312 46.930 39.336 ;
    END
  END addr_in_B[2]
  PIN addr_in_A[3]
    DIRECTION INPUT ;
    USE SIGNAL ;
    SHAPE ABUTMENT ;
    PORT
      LAYER M4 ;
      RECT 0.000 39.504 0.024 39.528 ;
    END
  END addr_in_A[3]
  PIN addr_in_B[3]
    DIRECTION INPUT ;
    USE SIGNAL ;
    SHAPE ABUTMENT ;
    PORT
      LAYER M4 ;
      RECT 46.906 39.504 46.930 39.528 ;
    END
  END addr_in_B[3]
  PIN addr_in_A[4]
    DIRECTION INPUT ;
    USE SIGNAL ;
    SHAPE ABUTMENT ;
    PORT
      LAYER M4 ;
      RECT 0.000 39.696 0.024 39.720 ;
    END
  END addr_in_A[4]
  PIN addr_in_B[4]
    DIRECTION INPUT ;
    USE SIGNAL ;
    SHAPE ABUTMENT ;
    PORT
      LAYER M4 ;
      RECT 46.906 39.696 46.930 39.720 ;
    END
  END addr_in_B[4]
  PIN addr_in_A[5]
    DIRECTION INPUT ;
    USE SIGNAL ;
    SHAPE ABUTMENT ;
    PORT
      LAYER M4 ;
      RECT 0.000 39.888 0.024 39.912 ;
    END
  END addr_in_A[5]
  PIN addr_in_B[5]
    DIRECTION INPUT ;
    USE SIGNAL ;
    SHAPE ABUTMENT ;
    PORT
      LAYER M4 ;
      RECT 46.906 39.888 46.930 39.912 ;
    END
  END addr_in_B[5]
  PIN addr_in_A[6]
    DIRECTION INPUT ;
    USE SIGNAL ;
    SHAPE ABUTMENT ;
    PORT
      LAYER M4 ;
      RECT 0.000 40.080 0.024 40.104 ;
    END
  END addr_in_A[6]
  PIN addr_in_B[6]
    DIRECTION INPUT ;
    USE SIGNAL ;
    SHAPE ABUTMENT ;
    PORT
      LAYER M4 ;
      RECT 46.906 40.080 46.930 40.104 ;
    END
  END addr_in_B[6]
  PIN addr_in_A[7]
    DIRECTION INPUT ;
    USE SIGNAL ;
    SHAPE ABUTMENT ;
    PORT
      LAYER M4 ;
      RECT 0.000 40.272 0.024 40.296 ;
    END
  END addr_in_A[7]
  PIN addr_in_B[7]
    DIRECTION INPUT ;
    USE SIGNAL ;
    SHAPE ABUTMENT ;
    PORT
      LAYER M4 ;
      RECT 46.906 40.272 46.930 40.296 ;
    END
  END addr_in_B[7]
  PIN addr_in_A[8]
    DIRECTION INPUT ;
    USE SIGNAL ;
    SHAPE ABUTMENT ;
    PORT
      LAYER M4 ;
      RECT 0.000 40.464 0.024 40.488 ;
    END
  END addr_in_A[8]
  PIN addr_in_B[8]
    DIRECTION INPUT ;
    USE SIGNAL ;
    SHAPE ABUTMENT ;
    PORT
      LAYER M4 ;
      RECT 46.906 40.464 46.930 40.488 ;
    END
  END addr_in_B[8]
  PIN we_in_A
    DIRECTION INPUT ;
    USE SIGNAL ;
    SHAPE ABUTMENT ;
    PORT
      LAYER M4 ;
      RECT 0.000 41.328 0.024 41.352 ;
    END
  END we_in_A
  PIN we_in_B
    DIRECTION INPUT ;
    USE SIGNAL ;
    SHAPE ABUTMENT ;
    PORT
      LAYER M4 ;
      RECT 46.906 41.328 46.930 41.352 ;
    END
  END we_in_B
  PIN ce_in
    DIRECTION INPUT ;
    USE SIGNAL ;
    SHAPE ABUTMENT ;
    PORT
      LAYER M4 ;
      RECT 0.000 41.520 0.024 41.544 ;
    END
  END ce_in
  PIN clk
    DIRECTION INPUT ;
    USE SIGNAL ;
    SHAPE ABUTMENT ;
    PORT
      LAYER M4 ;
      RECT 0.000 41.712 0.024 41.736 ;
    END
  END clk
  PIN VSS
    DIRECTION INOUT ;
    USE GROUND ;
    PORT
      LAYER M4 ;
      RECT 0.048 0.000 46.882 0.096 ;
      RECT 0.048 0.768 46.882 0.864 ;
      RECT 0.048 1.536 46.882 1.632 ;
      RECT 0.048 2.304 46.882 2.400 ;
      RECT 0.048 3.072 46.882 3.168 ;
      RECT 0.048 3.840 46.882 3.936 ;
      RECT 0.048 4.608 46.882 4.704 ;
      RECT 0.048 5.376 46.882 5.472 ;
      RECT 0.048 6.144 46.882 6.240 ;
      RECT 0.048 6.912 46.882 7.008 ;
      RECT 0.048 7.680 46.882 7.776 ;
      RECT 0.048 8.448 46.882 8.544 ;
      RECT 0.048 9.216 46.882 9.312 ;
      RECT 0.048 9.984 46.882 10.080 ;
      RECT 0.048 10.752 46.882 10.848 ;
      RECT 0.048 11.520 46.882 11.616 ;
      RECT 0.048 12.288 46.882 12.384 ;
      RECT 0.048 13.056 46.882 13.152 ;
      RECT 0.048 13.824 46.882 13.920 ;
      RECT 0.048 14.592 46.882 14.688 ;
      RECT 0.048 15.360 46.882 15.456 ;
      RECT 0.048 16.128 46.882 16.224 ;
      RECT 0.048 16.896 46.882 16.992 ;
      RECT 0.048 17.664 46.882 17.760 ;
      RECT 0.048 18.432 46.882 18.528 ;
      RECT 0.048 19.200 46.882 19.296 ;
      RECT 0.048 19.968 46.882 20.064 ;
      RECT 0.048 20.736 46.882 20.832 ;
      RECT 0.048 21.504 46.882 21.600 ;
      RECT 0.048 22.272 46.882 22.368 ;
      RECT 0.048 23.040 46.882 23.136 ;
      RECT 0.048 23.808 46.882 23.904 ;
      RECT 0.048 24.576 46.882 24.672 ;
      RECT 0.048 25.344 46.882 25.440 ;
      RECT 0.048 26.112 46.882 26.208 ;
      RECT 0.048 26.880 46.882 26.976 ;
      RECT 0.048 27.648 46.882 27.744 ;
      RECT 0.048 28.416 46.882 28.512 ;
      RECT 0.048 29.184 46.882 29.280 ;
      RECT 0.048 29.952 46.882 30.048 ;
      RECT 0.048 30.720 46.882 30.816 ;
      RECT 0.048 31.488 46.882 31.584 ;
      RECT 0.048 32.256 46.882 32.352 ;
      RECT 0.048 33.024 46.882 33.120 ;
      RECT 0.048 33.792 46.882 33.888 ;
      RECT 0.048 34.560 46.882 34.656 ;
      RECT 0.048 35.328 46.882 35.424 ;
      RECT 0.048 36.096 46.882 36.192 ;
      RECT 0.048 36.864 46.882 36.960 ;
      RECT 0.048 37.632 46.882 37.728 ;
      RECT 0.048 38.400 46.882 38.496 ;
      RECT 0.048 39.168 46.882 39.264 ;
      RECT 0.048 39.936 46.882 40.032 ;
      RECT 0.048 40.704 46.882 40.800 ;
      RECT 0.048 41.472 46.882 41.568 ;
    END
  END VSS
  PIN VDD
    DIRECTION INOUT ;
    USE POWER ;
    PORT
      LAYER M4 ;
      RECT 0.048 0.384 46.882 0.480 ;
      RECT 0.048 1.152 46.882 1.248 ;
      RECT 0.048 1.920 46.882 2.016 ;
      RECT 0.048 2.688 46.882 2.784 ;
      RECT 0.048 3.456 46.882 3.552 ;
      RECT 0.048 4.224 46.882 4.320 ;
      RECT 0.048 4.992 46.882 5.088 ;
      RECT 0.048 5.760 46.882 5.856 ;
      RECT 0.048 6.528 46.882 6.624 ;
      RECT 0.048 7.296 46.882 7.392 ;
      RECT 0.048 8.064 46.882 8.160 ;
      RECT 0.048 8.832 46.882 8.928 ;
      RECT 0.048 9.600 46.882 9.696 ;
      RECT 0.048 10.368 46.882 10.464 ;
      RECT 0.048 11.136 46.882 11.232 ;
      RECT 0.048 11.904 46.882 12.000 ;
      RECT 0.048 12.672 46.882 12.768 ;
      RECT 0.048 13.440 46.882 13.536 ;
      RECT 0.048 14.208 46.882 14.304 ;
      RECT 0.048 14.976 46.882 15.072 ;
      RECT 0.048 15.744 46.882 15.840 ;
      RECT 0.048 16.512 46.882 16.608 ;
      RECT 0.048 17.280 46.882 17.376 ;
      RECT 0.048 18.048 46.882 18.144 ;
      RECT 0.048 18.816 46.882 18.912 ;
      RECT 0.048 19.584 46.882 19.680 ;
      RECT 0.048 20.352 46.882 20.448 ;
      RECT 0.048 21.120 46.882 21.216 ;
      RECT 0.048 21.888 46.882 21.984 ;
      RECT 0.048 22.656 46.882 22.752 ;
      RECT 0.048 23.424 46.882 23.520 ;
      RECT 0.048 24.192 46.882 24.288 ;
      RECT 0.048 24.960 46.882 25.056 ;
      RECT 0.048 25.728 46.882 25.824 ;
      RECT 0.048 26.496 46.882 26.592 ;
      RECT 0.048 27.264 46.882 27.360 ;
      RECT 0.048 28.032 46.882 28.128 ;
      RECT 0.048 28.800 46.882 28.896 ;
      RECT 0.048 29.568 46.882 29.664 ;
      RECT 0.048 30.336 46.882 30.432 ;
      RECT 0.048 31.104 46.882 31.200 ;
      RECT 0.048 31.872 46.882 31.968 ;
      RECT 0.048 32.640 46.882 32.736 ;
      RECT 0.048 33.408 46.882 33.504 ;
      RECT 0.048 34.176 46.882 34.272 ;
      RECT 0.048 34.944 46.882 35.040 ;
      RECT 0.048 35.712 46.882 35.808 ;
      RECT 0.048 36.480 46.882 36.576 ;
      RECT 0.048 37.248 46.882 37.344 ;
      RECT 0.048 38.016 46.882 38.112 ;
      RECT 0.048 38.784 46.882 38.880 ;
      RECT 0.048 39.552 46.882 39.648 ;
      RECT 0.048 40.320 46.882 40.416 ;
      RECT 0.048 41.088 46.882 41.184 ;
      RECT 0.048 41.856 46.882 41.952 ;
    END
  END VDD
  OBS
    LAYER M1 ;
    RECT 0 0 46.930 42.000 ;
    LAYER M2 ;
    RECT 0 0 46.930 42.000 ;
    LAYER M3 ;
    RECT 0 0 46.930 42.000 ;
    LAYER M4 ;
    RECT 0 0 46.930 42.000 ;
  END
END fakeram7_dp_512x64

END LIBRARY
